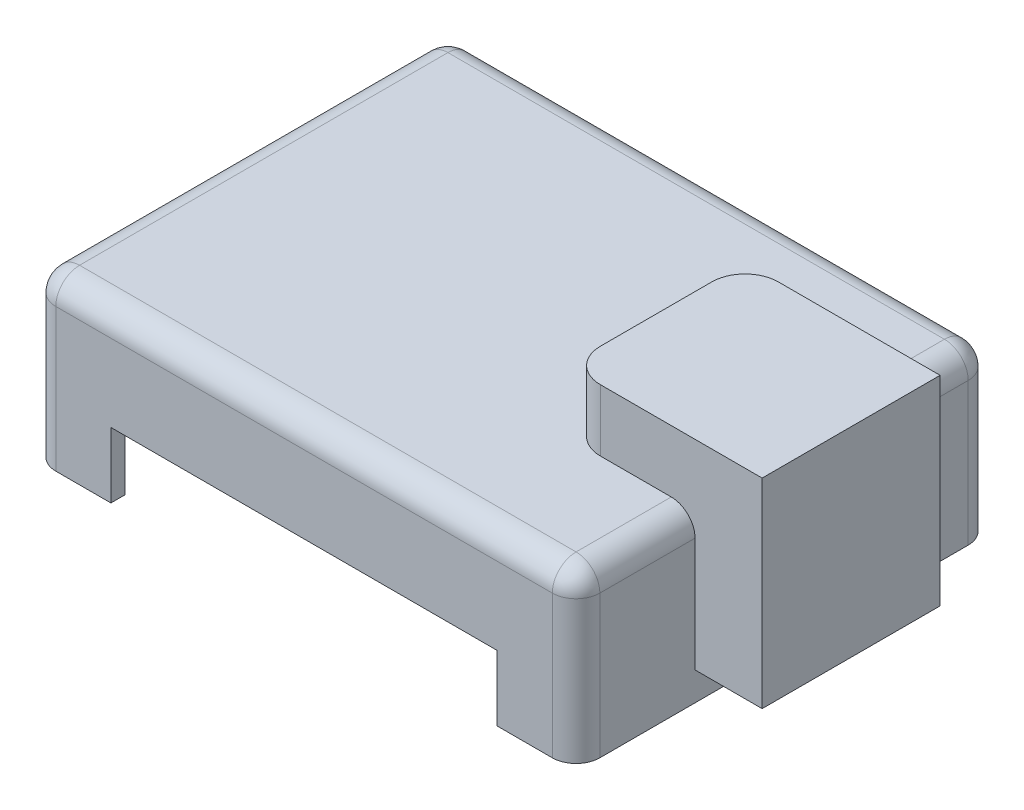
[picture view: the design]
ISO-10303-21;
HEADER;
FILE_DESCRIPTION(('STEP AP214'),'2;1');
FILE_NAME('part.step','',(''),(''),'','','');
FILE_SCHEMA(('AUTOMOTIVE_DESIGN { 1 0 10303 214 1 1 1 1 }'));
ENDSEC;
DATA;
#1=APPLICATION_CONTEXT('core data for automotive mechanical design processes');
#2=APPLICATION_PROTOCOL_DEFINITION('international standard','automotive_design',2000,#1);
#3=PRODUCT_CONTEXT('',#1,'mechanical');
#4=PRODUCT('Part','Part','',(#3));
#5=PRODUCT_RELATED_PRODUCT_CATEGORY('part','',(#4));
#6=PRODUCT_DEFINITION_FORMATION('','',#4);
#7=PRODUCT_DEFINITION_CONTEXT('part definition',#1,'design');
#8=PRODUCT_DEFINITION('design','',#6,#7);
#9=PRODUCT_DEFINITION_SHAPE('','',#8);
#10=(LENGTH_UNIT() NAMED_UNIT(*) SI_UNIT(.MILLI.,.METRE.));
#11=(NAMED_UNIT(*) PLANE_ANGLE_UNIT() SI_UNIT($,.RADIAN.));
#12=(NAMED_UNIT(*) SI_UNIT($,.STERADIAN.) SOLID_ANGLE_UNIT());
#13=UNCERTAINTY_MEASURE_WITH_UNIT(LENGTH_MEASURE(1.E-05),#10,'distance_accuracy_value','');
#14=(GEOMETRIC_REPRESENTATION_CONTEXT(3) GLOBAL_UNCERTAINTY_ASSIGNED_CONTEXT((#13)) GLOBAL_UNIT_ASSIGNED_CONTEXT((#10,
#11,#12)) REPRESENTATION_CONTEXT('',''));
#15=CARTESIAN_POINT('',(0.,0.,0.));
#16=DIRECTION('',(0.,0.,1.));
#17=DIRECTION('',(1.,0.,0.));
#18=AXIS2_PLACEMENT_3D('',#15,#16,#17);
#19=CARTESIAN_POINT('',(71.3184047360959,48.,-18.7130463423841));
#20=DIRECTION('',(-1.,0.,0.));
#21=DIRECTION('',(0.,0.,1.));
#22=AXIS2_PLACEMENT_3D('',#19,#20,#21);
#23=PLANE('',#22);
#24=DIRECTION('',(0.,-1.,0.));
#25=VECTOR('',#24,1.);
#26=CARTESIAN_POINT('',(71.3184047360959,48.,18.7130463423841));
#27=LINE('',#26,#25);
#28=CARTESIAN_POINT('',(71.3184047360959,48.,18.7130463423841));
#29=VERTEX_POINT('',#28);
#30=CARTESIAN_POINT('',(71.3184047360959,6.00000000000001,18.7130463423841));
#31=VERTEX_POINT('',#30);
#32=EDGE_CURVE('E114',#29,#31,#27,.T.);
#33=ORIENTED_EDGE('',*,*,#32,.T.);
#34=DIRECTION('',(0.,0.,-1.));
#35=VECTOR('',#34,1.);
#36=CARTESIAN_POINT('',(71.3184047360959,6.00000000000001,-18.7130463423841));
#37=LINE('',#36,#35);
#38=CARTESIAN_POINT('',(71.3184047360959,6.00000000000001,-18.7130463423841));
#39=VERTEX_POINT('',#38);
#40=EDGE_CURVE('E108',#31,#39,#37,.T.);
#41=ORIENTED_EDGE('',*,*,#40,.T.);
#42=DIRECTION('',(0.,-1.,0.));
#43=VECTOR('',#42,1.);
#44=CARTESIAN_POINT('',(71.3184047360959,48.,-18.7130463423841));
#45=LINE('',#44,#43);
#46=CARTESIAN_POINT('',(71.3184047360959,48.,-18.7130463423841));
#47=VERTEX_POINT('',#46);
#48=EDGE_CURVE('E12',#47,#39,#45,.T.);
#49=ORIENTED_EDGE('',*,*,#48,.F.);
#50=DIRECTION('',(0.,0.,-1.));
#51=VECTOR('',#50,1.);
#52=CARTESIAN_POINT('',(71.3184047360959,48.,-18.7130463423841));
#53=LINE('',#52,#51);
#54=EDGE_CURVE('E126',#29,#47,#53,.T.);
#55=ORIENTED_EDGE('',*,*,#54,.F.);
#56=EDGE_LOOP('',(#33,#41,#49,#55));
#57=FACE_BOUND('',#56,.T.);
#58=ADVANCED_FACE('F44',(#57),#23,.F.);
#59=CARTESIAN_POINT('',(37.3006394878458,48.,-18.7130463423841));
#60=DIRECTION('',(0.,0.,1.));
#61=DIRECTION('',(1.,0.,0.));
#62=AXIS2_PLACEMENT_3D('',#59,#60,#61);
#63=PLANE('',#62);
#64=ORIENTED_EDGE('',*,*,#48,.T.);
#65=DIRECTION('',(-1.,0.,0.));
#66=VECTOR('',#65,1.);
#67=CARTESIAN_POINT('',(37.3006394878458,6.00000000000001,-18.7130463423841));
#68=LINE('',#67,#66);
#69=CARTESIAN_POINT('',(37.3006394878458,6.00000000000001,-18.7130463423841));
#70=VERTEX_POINT('',#69);
#71=EDGE_CURVE('E98',#39,#70,#68,.T.);
#72=ORIENTED_EDGE('',*,*,#71,.T.);
#73=DIRECTION('',(0.,-1.,0.));
#74=VECTOR('',#73,1.);
#75=CARTESIAN_POINT('',(37.3006394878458,48.,-18.7130463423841));
#76=LINE('',#75,#74);
#77=CARTESIAN_POINT('',(37.3006394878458,48.,-18.7130463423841));
#78=VERTEX_POINT('',#77);
#79=EDGE_CURVE('E51',#78,#70,#76,.T.);
#80=ORIENTED_EDGE('',*,*,#79,.F.);
#81=DIRECTION('',(-1.,0.,0.));
#82=VECTOR('',#81,1.);
#83=CARTESIAN_POINT('',(37.3006394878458,48.,-18.7130463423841));
#84=LINE('',#83,#82);
#85=EDGE_CURVE('E99',#47,#78,#84,.T.);
#86=ORIENTED_EDGE('',*,*,#85,.F.);
#87=EDGE_LOOP('',(#64,#72,#80,#86));
#88=FACE_BOUND('',#87,.T.);
#89=ADVANCED_FACE('F96',(#88),#63,.F.);
#90=CARTESIAN_POINT('',(37.3006394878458,48.,-11.7130463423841));
#91=DIRECTION('',(0.,-1.,0.));
#92=DIRECTION('',(0.,0.,-1.));
#93=AXIS2_PLACEMENT_3D('',#90,#91,#92);
#94=CYLINDRICAL_SURFACE('',#93,7.);
#95=ORIENTED_EDGE('',*,*,#79,.T.);
#96=CARTESIAN_POINT('',(37.3006394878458,6.00000000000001,-11.7130463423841));
#97=DIRECTION('',(0.,1.,0.));
#98=DIRECTION('',(0.,0.,1.));
#99=AXIS2_PLACEMENT_3D('',#96,#97,#98);
#100=CIRCLE('',#99,7.);
#101=CARTESIAN_POINT('',(30.3006394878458,6.00000000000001,-11.7130463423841));
#102=VERTEX_POINT('',#101);
#103=EDGE_CURVE('E112',#70,#102,#100,.T.);
#104=ORIENTED_EDGE('',*,*,#103,.T.);
#105=DIRECTION('',(0.,-1.,0.));
#106=VECTOR('',#105,1.);
#107=CARTESIAN_POINT('',(30.3006394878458,48.,-11.7130463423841));
#108=LINE('',#107,#106);
#109=CARTESIAN_POINT('',(30.3006394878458,48.,-11.7130463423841));
#110=VERTEX_POINT('',#109);
#111=EDGE_CURVE('E140',#110,#102,#108,.T.);
#112=ORIENTED_EDGE('',*,*,#111,.F.);
#113=CARTESIAN_POINT('',(37.3006394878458,48.,-11.7130463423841));
#114=DIRECTION('',(0.,1.,0.));
#115=DIRECTION('',(0.,0.,1.));
#116=AXIS2_PLACEMENT_3D('',#113,#114,#115);
#117=CIRCLE('',#116,7.);
#118=EDGE_CURVE('E129',#78,#110,#117,.T.);
#119=ORIENTED_EDGE('',*,*,#118,.F.);
#120=EDGE_LOOP('',(#95,#104,#112,#119));
#121=FACE_BOUND('',#120,.T.);
#122=ADVANCED_FACE('F143',(#121),#94,.T.);
#123=CARTESIAN_POINT('',(30.3006394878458,48.,-11.7130463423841));
#124=DIRECTION('',(1.,0.,0.));
#125=DIRECTION('',(0.,0.,-1.));
#126=AXIS2_PLACEMENT_3D('',#123,#124,#125);
#127=PLANE('',#126);
#128=ORIENTED_EDGE('',*,*,#111,.T.);
#129=DIRECTION('',(0.,0.,1.));
#130=VECTOR('',#129,1.);
#131=CARTESIAN_POINT('',(30.3006394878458,6.00000000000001,-11.7130463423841));
#132=LINE('',#131,#130);
#133=CARTESIAN_POINT('',(30.3006394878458,6.00000000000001,11.7130463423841));
#134=VERTEX_POINT('',#133);
#135=EDGE_CURVE('E118',#102,#134,#132,.T.);
#136=ORIENTED_EDGE('',*,*,#135,.T.);
#137=DIRECTION('',(0.,-1.,0.));
#138=VECTOR('',#137,1.);
#139=CARTESIAN_POINT('',(30.3006394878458,48.,11.7130463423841));
#140=LINE('',#139,#138);
#141=CARTESIAN_POINT('',(30.3006394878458,48.,11.7130463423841));
#142=VERTEX_POINT('',#141);
#143=EDGE_CURVE('E138',#142,#134,#140,.T.);
#144=ORIENTED_EDGE('',*,*,#143,.F.);
#145=DIRECTION('',(0.,0.,1.));
#146=VECTOR('',#145,1.);
#147=CARTESIAN_POINT('',(30.3006394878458,48.,-11.7130463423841));
#148=LINE('',#147,#146);
#149=EDGE_CURVE('E131',#110,#142,#148,.T.);
#150=ORIENTED_EDGE('',*,*,#149,.F.);
#151=EDGE_LOOP('',(#128,#136,#144,#150));
#152=FACE_BOUND('',#151,.T.);
#153=ADVANCED_FACE('F149',(#152),#127,.F.);
#154=CARTESIAN_POINT('',(37.3006394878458,48.,11.7130463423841));
#155=DIRECTION('',(0.,-1.,0.));
#156=DIRECTION('',(0.,0.,-1.));
#157=AXIS2_PLACEMENT_3D('',#154,#155,#156);
#158=CYLINDRICAL_SURFACE('',#157,7.);
#159=ORIENTED_EDGE('',*,*,#143,.T.);
#160=CARTESIAN_POINT('',(37.3006394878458,6.00000000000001,11.7130463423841));
#161=DIRECTION('',(0.,1.,0.));
#162=DIRECTION('',(0.,0.,1.));
#163=AXIS2_PLACEMENT_3D('',#160,#161,#162);
#164=CIRCLE('',#163,7.);
#165=CARTESIAN_POINT('',(37.3006394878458,6.00000000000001,18.7130463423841));
#166=VERTEX_POINT('',#165);
#167=EDGE_CURVE('E121',#134,#166,#164,.T.);
#168=ORIENTED_EDGE('',*,*,#167,.T.);
#169=DIRECTION('',(0.,-1.,0.));
#170=VECTOR('',#169,1.);
#171=CARTESIAN_POINT('',(37.3006394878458,48.,18.7130463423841));
#172=LINE('',#171,#170);
#173=CARTESIAN_POINT('',(37.3006394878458,48.,18.7130463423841));
#174=VERTEX_POINT('',#173);
#175=EDGE_CURVE('E136',#174,#166,#172,.T.);
#176=ORIENTED_EDGE('',*,*,#175,.F.);
#177=CARTESIAN_POINT('',(37.3006394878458,48.,11.7130463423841));
#178=DIRECTION('',(0.,1.,0.));
#179=DIRECTION('',(0.,0.,1.));
#180=AXIS2_PLACEMENT_3D('',#177,#178,#179);
#181=CIRCLE('',#180,7.);
#182=EDGE_CURVE('E63',#142,#174,#181,.T.);
#183=ORIENTED_EDGE('',*,*,#182,.F.);
#184=EDGE_LOOP('',(#159,#168,#176,#183));
#185=FACE_BOUND('',#184,.T.);
#186=ADVANCED_FACE('F152',(#185),#158,.T.);
#187=CARTESIAN_POINT('',(37.3006394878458,48.,18.7130463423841));
#188=DIRECTION('',(0.,0.,-1.));
#189=DIRECTION('',(-1.,0.,0.));
#190=AXIS2_PLACEMENT_3D('',#187,#188,#189);
#191=PLANE('',#190);
#192=ORIENTED_EDGE('',*,*,#175,.T.);
#193=DIRECTION('',(1.,0.,0.));
#194=VECTOR('',#193,1.);
#195=CARTESIAN_POINT('',(37.3006394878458,6.00000000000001,18.7130463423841));
#196=LINE('',#195,#194);
#197=EDGE_CURVE('E124',#166,#31,#196,.T.);
#198=ORIENTED_EDGE('',*,*,#197,.T.);
#199=ORIENTED_EDGE('',*,*,#32,.F.);
#200=DIRECTION('',(1.,0.,0.));
#201=VECTOR('',#200,1.);
#202=CARTESIAN_POINT('',(37.3006394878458,48.,18.7130463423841));
#203=LINE('',#202,#201);
#204=EDGE_CURVE('E58',#174,#29,#203,.T.);
#205=ORIENTED_EDGE('',*,*,#204,.F.);
#206=EDGE_LOOP('',(#192,#198,#199,#205));
#207=FACE_BOUND('',#206,.T.);
#208=ADVANCED_FACE('F154',(#207),#191,.F.);
#209=CARTESIAN_POINT('',(37.3006394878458,48.,11.7130463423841));
#210=DIRECTION('',(0.,1.,0.));
#211=DIRECTION('',(0.,0.,1.));
#212=AXIS2_PLACEMENT_3D('',#209,#210,#211);
#213=PLANE('',#212);
#214=ORIENTED_EDGE('',*,*,#54,.T.);
#215=ORIENTED_EDGE('',*,*,#85,.T.);
#216=ORIENTED_EDGE('',*,*,#118,.T.);
#217=ORIENTED_EDGE('',*,*,#149,.T.);
#218=ORIENTED_EDGE('',*,*,#182,.T.);
#219=ORIENTED_EDGE('',*,*,#204,.T.);
#220=EDGE_LOOP('',(#214,#215,#216,#217,#218,#219));
#221=FACE_BOUND('',#220,.T.);
#222=ADVANCED_FACE('F146',(#221),#213,.T.);
#223=CARTESIAN_POINT('',(37.3006394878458,6.00000000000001,11.7130463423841));
#224=DIRECTION('',(0.,1.,0.));
#225=DIRECTION('',(0.,0.,1.));
#226=AXIS2_PLACEMENT_3D('',#223,#224,#225);
#227=PLANE('',#226);
#228=ORIENTED_EDGE('',*,*,#40,.F.);
#229=ORIENTED_EDGE('',*,*,#197,.F.);
#230=ORIENTED_EDGE('',*,*,#167,.F.);
#231=ORIENTED_EDGE('',*,*,#135,.F.);
#232=ORIENTED_EDGE('',*,*,#103,.F.);
#233=ORIENTED_EDGE('',*,*,#71,.F.);
#234=EDGE_LOOP('',(#228,#229,#230,#231,#232,#233));
#235=FACE_BOUND('',#234,.T.);
#236=ADVANCED_FACE('F106',(#235),#227,.F.);
#237=CLOSED_SHELL('',(#58,#89,#122,#153,#186,#208,#222,#236));
#238=MANIFOLD_SOLID_BREP('B2_NOT_SHOWN',#237);
#239=CARTESIAN_POINT('',(57.2074120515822,35.,-43.7327831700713));
#240=DIRECTION('',(-1.,0.,0.));
#241=DIRECTION('',(0.,0.,1.));
#242=AXIS2_PLACEMENT_3D('',#239,#240,#241);
#243=PLANE('',#242);
#244=DIRECTION('',(0.,1.,0.));
#245=VECTOR('',#244,1.);
#246=CARTESIAN_POINT('',(57.2074120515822,35.,-18.7130463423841));
#247=LINE('',#246,#245);
#248=CARTESIAN_POINT('',(57.2074120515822,6.00000000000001,-18.7130463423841));
#249=VERTEX_POINT('',#248);
#250=CARTESIAN_POINT('',(57.2074120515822,30.,-18.7130463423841));
#251=VERTEX_POINT('',#250);
#252=EDGE_CURVE('E451',#249,#251,#247,.T.);
#253=ORIENTED_EDGE('',*,*,#252,.F.);
#254=DIRECTION('',(0.,0.,-1.));
#255=VECTOR('',#254,1.);
#256=CARTESIAN_POINT('',(57.2074120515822,6.00000000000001,-43.7327831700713));
#257=LINE('',#256,#255);
#258=CARTESIAN_POINT('',(57.2074120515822,6.00000000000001,18.7130463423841));
#259=VERTEX_POINT('',#258);
#260=EDGE_CURVE('E485',#259,#249,#257,.T.);
#261=ORIENTED_EDGE('',*,*,#260,.F.);
#262=DIRECTION('',(0.,-1.,0.));
#263=VECTOR('',#262,1.);
#264=CARTESIAN_POINT('',(57.2074120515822,35.,18.7130463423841));
#265=LINE('',#264,#263);
#266=CARTESIAN_POINT('',(57.2074120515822,30.,18.7130463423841));
#267=VERTEX_POINT('',#266);
#268=EDGE_CURVE('E463',#267,#259,#265,.T.);
#269=ORIENTED_EDGE('',*,*,#268,.F.);
#270=DIRECTION('',(0.,0.,-1.));
#271=VECTOR('',#270,1.);
#272=CARTESIAN_POINT('',(57.2074120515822,30.,43.7327831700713));
#273=LINE('',#272,#271);
#274=CARTESIAN_POINT('',(57.2074120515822,30.,38.7327831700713));
#275=VERTEX_POINT('',#274);
#276=EDGE_CURVE('E673',#267,#275,#273,.F.);
#277=ORIENTED_EDGE('',*,*,#276,.T.);
#278=DIRECTION('',(0.,-1.,0.));
#279=VECTOR('',#278,1.);
#280=CARTESIAN_POINT('',(57.2074120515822,35.,38.7327831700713));
#281=LINE('',#280,#279);
#282=CARTESIAN_POINT('',(57.2074120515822,0.,38.7327831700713));
#283=VERTEX_POINT('',#282);
#284=EDGE_CURVE('E671',#275,#283,#281,.T.);
#285=ORIENTED_EDGE('',*,*,#284,.T.);
#286=DIRECTION('',(0.,0.,-1.));
#287=VECTOR('',#286,1.);
#288=CARTESIAN_POINT('',(57.2074120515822,0.,-43.7327831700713));
#289=LINE('',#288,#287);
#290=CARTESIAN_POINT('',(57.2074120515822,0.,-38.7327831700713));
#291=VERTEX_POINT('',#290);
#292=EDGE_CURVE('E649',#283,#291,#289,.T.);
#293=ORIENTED_EDGE('',*,*,#292,.T.);
#294=DIRECTION('',(0.,-1.,0.));
#295=VECTOR('',#294,1.);
#296=CARTESIAN_POINT('',(57.2074120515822,35.,-38.7327831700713));
#297=LINE('',#296,#295);
#298=CARTESIAN_POINT('',(57.2074120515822,30.,-38.7327831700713));
#299=VERTEX_POINT('',#298);
#300=EDGE_CURVE('E677',#291,#299,#297,.F.);
#301=ORIENTED_EDGE('',*,*,#300,.T.);
#302=EDGE_CURVE('E674',#299,#251,#273,.F.);
#303=ORIENTED_EDGE('',*,*,#302,.T.);
#304=EDGE_LOOP('',(#253,#261,#269,#277,#285,#293,#301,#303));
#305=FACE_BOUND('',#304,.T.);
#306=ADVANCED_FACE('F219',(#305),#243,.F.);
#307=CARTESIAN_POINT('',(-57.2074120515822,35.,43.7327831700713));
#308=DIRECTION('',(0.,1.,0.));
#309=DIRECTION('',(0.,0.,1.));
#310=AXIS2_PLACEMENT_3D('',#307,#308,#309);
#311=PLANE('',#310);
#312=CARTESIAN_POINT('',(37.3006394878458,35.,-11.7130463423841));
#313=DIRECTION('',(0.,1.,0.));
#314=DIRECTION('',(0.,0.,1.));
#315=AXIS2_PLACEMENT_3D('',#312,#313,#314);
#316=CIRCLE('',#315,7.);
#317=CARTESIAN_POINT('',(30.3006394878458,35.,-11.7130463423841));
#318=VERTEX_POINT('',#317);
#319=CARTESIAN_POINT('',(37.3006394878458,35.,-18.7130463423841));
#320=VERTEX_POINT('',#319);
#321=EDGE_CURVE('E483',#318,#320,#316,.F.);
#322=ORIENTED_EDGE('',*,*,#321,.T.);
#323=DIRECTION('',(1.,0.,0.));
#324=VECTOR('',#323,1.);
#325=CARTESIAN_POINT('',(-57.2074120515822,35.,-18.7130463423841));
#326=LINE('',#325,#324);
#327=CARTESIAN_POINT('',(52.2074120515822,35.,-18.7130463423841));
#328=VERTEX_POINT('',#327);
#329=EDGE_CURVE('E478',#320,#328,#326,.T.);
#330=ORIENTED_EDGE('',*,*,#329,.T.);
#331=DIRECTION('',(0.,0.,-1.));
#332=VECTOR('',#331,1.);
#333=CARTESIAN_POINT('',(52.2074120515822,35.,-43.7327831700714));
#334=LINE('',#333,#332);
#335=CARTESIAN_POINT('',(52.2074120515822,35.,-38.7327831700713));
#336=VERTEX_POINT('',#335);
#337=EDGE_CURVE('E659',#328,#336,#334,.T.);
#338=ORIENTED_EDGE('',*,*,#337,.T.);
#339=DIRECTION('',(-1.,0.,0.));
#340=VECTOR('',#339,1.);
#341=CARTESIAN_POINT('',(-57.2074120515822,35.,-38.7327831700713));
#342=LINE('',#341,#340);
#343=CARTESIAN_POINT('',(-52.2074120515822,35.,-38.7327831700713));
#344=VERTEX_POINT('',#343);
#345=EDGE_CURVE('E661',#336,#344,#342,.T.);
#346=ORIENTED_EDGE('',*,*,#345,.T.);
#347=DIRECTION('',(0.,0.,1.));
#348=VECTOR('',#347,1.);
#349=CARTESIAN_POINT('',(-52.2074120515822,35.,43.7327831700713));
#350=LINE('',#349,#348);
#351=CARTESIAN_POINT('',(-52.2074120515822,35.,38.7327831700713));
#352=VERTEX_POINT('',#351);
#353=EDGE_CURVE('E655',#344,#352,#350,.T.);
#354=ORIENTED_EDGE('',*,*,#353,.T.);
#355=DIRECTION('',(1.,0.,0.));
#356=VECTOR('',#355,1.);
#357=CARTESIAN_POINT('',(57.2074120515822,35.,38.7327831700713));
#358=LINE('',#357,#356);
#359=CARTESIAN_POINT('',(52.2074120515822,35.,38.7327831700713));
#360=VERTEX_POINT('',#359);
#361=EDGE_CURVE('E657',#352,#360,#358,.T.);
#362=ORIENTED_EDGE('',*,*,#361,.T.);
#363=CARTESIAN_POINT('',(52.2074120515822,35.,18.7130463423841));
#364=VERTEX_POINT('',#363);
#365=EDGE_CURVE('E462',#360,#364,#334,.T.);
#366=ORIENTED_EDGE('',*,*,#365,.T.);
#367=DIRECTION('',(-1.,0.,0.));
#368=VECTOR('',#367,1.);
#369=CARTESIAN_POINT('',(-57.2074120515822,35.,18.7130463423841));
#370=LINE('',#369,#368);
#371=CARTESIAN_POINT('',(37.3006394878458,35.,18.7130463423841));
#372=VERTEX_POINT('',#371);
#373=EDGE_CURVE('E234',#364,#372,#370,.T.);
#374=ORIENTED_EDGE('',*,*,#373,.T.);
#375=CARTESIAN_POINT('',(37.3006394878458,35.,11.7130463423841));
#376=DIRECTION('',(0.,1.,0.));
#377=DIRECTION('',(0.,0.,1.));
#378=AXIS2_PLACEMENT_3D('',#375,#376,#377);
#379=CIRCLE('',#378,7.);
#380=CARTESIAN_POINT('',(30.3006394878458,35.,11.7130463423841));
#381=VERTEX_POINT('',#380);
#382=EDGE_CURVE('E442',#372,#381,#379,.F.);
#383=ORIENTED_EDGE('',*,*,#382,.T.);
#384=DIRECTION('',(0.,0.,-1.));
#385=VECTOR('',#384,1.);
#386=CARTESIAN_POINT('',(30.3006394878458,35.,43.7327831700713));
#387=LINE('',#386,#385);
#388=EDGE_CURVE('E450',#381,#318,#387,.T.);
#389=ORIENTED_EDGE('',*,*,#388,.T.);
#390=EDGE_LOOP('',(#322,#330,#338,#346,#354,#362,#366,#374,#383,#389));
#391=FACE_BOUND('',#390,.T.);
#392=ADVANCED_FACE('F460',(#391),#311,.T.);
#393=CARTESIAN_POINT('',(52.2074120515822,30.,43.7327831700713));
#394=DIRECTION('',(0.,0.,1.));
#395=DIRECTION('',(1.,0.,0.));
#396=AXIS2_PLACEMENT_3D('',#393,#394,#395);
#397=CYLINDRICAL_SURFACE('',#396,5.);
#398=ORIENTED_EDGE('',*,*,#337,.F.);
#399=CARTESIAN_POINT('',(52.2074120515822,30.,-18.7130463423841));
#400=DIRECTION('',(0.,0.,1.));
#401=DIRECTION('',(1.,0.,0.));
#402=AXIS2_PLACEMENT_3D('',#399,#400,#401);
#403=CIRCLE('',#402,5.);
#404=EDGE_CURVE('E475',#328,#251,#403,.F.);
#405=ORIENTED_EDGE('',*,*,#404,.T.);
#406=ORIENTED_EDGE('',*,*,#302,.F.);
#407=CARTESIAN_POINT('',(52.2074120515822,30.,-38.7327831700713));
#408=DIRECTION('',(0.,0.,-1.));
#409=DIRECTION('',(-1.,0.,0.));
#410=AXIS2_PLACEMENT_3D('',#407,#408,#409);
#411=CIRCLE('',#410,5.);
#412=EDGE_CURVE('E618',#336,#299,#411,.T.);
#413=ORIENTED_EDGE('',*,*,#412,.F.);
#414=EDGE_LOOP('',(#398,#405,#406,#413));
#415=FACE_BOUND('',#414,.T.);
#416=ADVANCED_FACE('F776',(#415),#397,.T.);
#417=ORIENTED_EDGE('',*,*,#276,.F.);
#418=CARTESIAN_POINT('',(52.2074120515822,30.,18.7130463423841));
#419=DIRECTION('',(0.,0.,-1.));
#420=DIRECTION('',(-1.,0.,0.));
#421=AXIS2_PLACEMENT_3D('',#418,#419,#420);
#422=CIRCLE('',#421,5.);
#423=EDGE_CURVE('E464',#267,#364,#422,.F.);
#424=ORIENTED_EDGE('',*,*,#423,.T.);
#425=ORIENTED_EDGE('',*,*,#365,.F.);
#426=CARTESIAN_POINT('',(52.2074120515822,30.,38.7327831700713));
#427=DIRECTION('',(0.,0.,1.));
#428=DIRECTION('',(1.,0.,0.));
#429=AXIS2_PLACEMENT_3D('',#426,#427,#428);
#430=CIRCLE('',#429,5.);
#431=EDGE_CURVE('E627',#360,#275,#430,.F.);
#432=ORIENTED_EDGE('',*,*,#431,.T.);
#433=EDGE_LOOP('',(#417,#424,#425,#432));
#434=FACE_BOUND('',#433,.T.);
#435=ADVANCED_FACE('F835',(#434),#397,.T.);
#436=CARTESIAN_POINT('',(54.2074120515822,35.,-43.7327831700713));
#437=DIRECTION('',(-1.,0.,0.));
#438=DIRECTION('',(0.,0.,1.));
#439=AXIS2_PLACEMENT_3D('',#436,#437,#438);
#440=PLANE('',#439);
#441=DIRECTION('',(0.,0.,-1.));
#442=VECTOR('',#441,1.);
#443=CARTESIAN_POINT('',(54.2074120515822,6.00000000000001,-43.7327831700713));
#444=LINE('',#443,#442);
#445=CARTESIAN_POINT('',(54.2074120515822,6.00000000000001,18.7130463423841));
#446=VERTEX_POINT('',#445);
#447=CARTESIAN_POINT('',(54.2074120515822,6.00000000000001,-18.7130463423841));
#448=VERTEX_POINT('',#447);
#449=EDGE_CURVE('E42',#446,#448,#444,.T.);
#450=ORIENTED_EDGE('',*,*,#449,.T.);
#451=DIRECTION('',(0.,1.,0.));
#452=VECTOR('',#451,1.);
#453=CARTESIAN_POINT('',(54.2074120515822,35.,-18.7130463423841));
#454=LINE('',#453,#452);
#455=CARTESIAN_POINT('',(54.2074120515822,30.,-18.7130463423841));
#456=VERTEX_POINT('',#455);
#457=EDGE_CURVE('E472',#448,#456,#454,.T.);
#458=ORIENTED_EDGE('',*,*,#457,.T.);
#459=DIRECTION('',(0.,0.,1.));
#460=VECTOR('',#459,1.);
#461=CARTESIAN_POINT('',(54.2074120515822,30.,-43.7327831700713));
#462=LINE('',#461,#460);
#463=CARTESIAN_POINT('',(54.2074120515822,30.,-38.7327831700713));
#464=VERTEX_POINT('',#463);
#465=EDGE_CURVE('E544',#464,#456,#462,.T.);
#466=ORIENTED_EDGE('',*,*,#465,.F.);
#467=DIRECTION('',(0.,1.,0.));
#468=VECTOR('',#467,1.);
#469=CARTESIAN_POINT('',(54.2074120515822,35.,-38.7327831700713));
#470=LINE('',#469,#468);
#471=CARTESIAN_POINT('',(54.2074120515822,0.,-38.7327831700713));
#472=VERTEX_POINT('',#471);
#473=EDGE_CURVE('E526',#472,#464,#470,.T.);
#474=ORIENTED_EDGE('',*,*,#473,.F.);
#475=DIRECTION('',(0.,0.,-1.));
#476=VECTOR('',#475,1.);
#477=CARTESIAN_POINT('',(54.2074120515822,0.,-43.7327831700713));
#478=LINE('',#477,#476);
#479=CARTESIAN_POINT('',(54.2074120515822,0.,38.7327831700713));
#480=VERTEX_POINT('',#479);
#481=EDGE_CURVE('E598',#480,#472,#478,.T.);
#482=ORIENTED_EDGE('',*,*,#481,.F.);
#483=DIRECTION('',(0.,1.,0.));
#484=VECTOR('',#483,1.);
#485=CARTESIAN_POINT('',(54.2074120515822,35.,38.7327831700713));
#486=LINE('',#485,#484);
#487=CARTESIAN_POINT('',(54.2074120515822,30.,38.7327831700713));
#488=VERTEX_POINT('',#487);
#489=EDGE_CURVE('E534',#488,#480,#486,.F.);
#490=ORIENTED_EDGE('',*,*,#489,.F.);
#491=CARTESIAN_POINT('',(54.2074120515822,30.,18.7130463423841));
#492=VERTEX_POINT('',#491);
#493=EDGE_CURVE('E536',#492,#488,#462,.T.);
#494=ORIENTED_EDGE('',*,*,#493,.F.);
#495=DIRECTION('',(0.,-1.,0.));
#496=VECTOR('',#495,1.);
#497=CARTESIAN_POINT('',(54.2074120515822,35.,18.7130463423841));
#498=LINE('',#497,#496);
#499=EDGE_CURVE('E241',#492,#446,#498,.T.);
#500=ORIENTED_EDGE('',*,*,#499,.T.);
#501=EDGE_LOOP('',(#450,#458,#466,#474,#482,#490,#494,#500));
#502=FACE_BOUND('',#501,.T.);
#503=ADVANCED_FACE('F750',(#502),#440,.T.);
#504=CARTESIAN_POINT('',(-57.2074120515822,32.,43.7327831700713));
#505=DIRECTION('',(0.,1.,0.));
#506=DIRECTION('',(0.,0.,1.));
#507=AXIS2_PLACEMENT_3D('',#504,#505,#506);
#508=PLANE('',#507);
#509=DIRECTION('',(1.,0.,0.));
#510=VECTOR('',#509,1.);
#511=CARTESIAN_POINT('',(-57.2074120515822,32.,-18.7130463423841));
#512=LINE('',#511,#510);
#513=CARTESIAN_POINT('',(37.3006394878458,32.,-18.7130463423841));
#514=VERTEX_POINT('',#513);
#515=CARTESIAN_POINT('',(52.2074120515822,32.,-18.7130463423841));
#516=VERTEX_POINT('',#515);
#517=EDGE_CURVE('E466',#514,#516,#512,.T.);
#518=ORIENTED_EDGE('',*,*,#517,.F.);
#519=CARTESIAN_POINT('',(37.3006394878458,32.,-11.7130463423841));
#520=DIRECTION('',(0.,1.,0.));
#521=DIRECTION('',(0.,0.,1.));
#522=AXIS2_PLACEMENT_3D('',#519,#520,#521);
#523=CIRCLE('',#522,7.);
#524=CARTESIAN_POINT('',(30.3006394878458,32.,-11.7130463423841));
#525=VERTEX_POINT('',#524);
#526=EDGE_CURVE('E227',#525,#514,#523,.F.);
#527=ORIENTED_EDGE('',*,*,#526,.F.);
#528=DIRECTION('',(0.,0.,-1.));
#529=VECTOR('',#528,1.);
#530=CARTESIAN_POINT('',(30.3006394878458,32.,43.7327831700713));
#531=LINE('',#530,#529);
#532=CARTESIAN_POINT('',(30.3006394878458,32.,11.7130463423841));
#533=VERTEX_POINT('',#532);
#534=EDGE_CURVE('E706',#533,#525,#531,.T.);
#535=ORIENTED_EDGE('',*,*,#534,.F.);
#536=CARTESIAN_POINT('',(37.3006394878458,32.,11.7130463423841));
#537=DIRECTION('',(0.,1.,0.));
#538=DIRECTION('',(0.,0.,1.));
#539=AXIS2_PLACEMENT_3D('',#536,#537,#538);
#540=CIRCLE('',#539,7.);
#541=CARTESIAN_POINT('',(37.3006394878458,32.,18.7130463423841));
#542=VERTEX_POINT('',#541);
#543=EDGE_CURVE('E704',#542,#533,#540,.F.);
#544=ORIENTED_EDGE('',*,*,#543,.F.);
#545=DIRECTION('',(-1.,0.,0.));
#546=VECTOR('',#545,1.);
#547=CARTESIAN_POINT('',(-57.2074120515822,32.,18.7130463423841));
#548=LINE('',#547,#546);
#549=CARTESIAN_POINT('',(52.2074120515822,32.,18.7130463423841));
#550=VERTEX_POINT('',#549);
#551=EDGE_CURVE('E455',#550,#542,#548,.T.);
#552=ORIENTED_EDGE('',*,*,#551,.F.);
#553=DIRECTION('',(0.,0.,1.));
#554=VECTOR('',#553,1.);
#555=CARTESIAN_POINT('',(52.2074120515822,32.,43.7327831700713));
#556=LINE('',#555,#554);
#557=CARTESIAN_POINT('',(52.2074120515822,32.,38.7327831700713));
#558=VERTEX_POINT('',#557);
#559=EDGE_CURVE('E552',#558,#550,#556,.F.);
#560=ORIENTED_EDGE('',*,*,#559,.F.);
#561=DIRECTION('',(1.,0.,0.));
#562=VECTOR('',#561,1.);
#563=CARTESIAN_POINT('',(-57.2074120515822,32.,38.7327831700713));
#564=LINE('',#563,#562);
#565=CARTESIAN_POINT('',(-52.2074120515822,32.,38.7327831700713));
#566=VERTEX_POINT('',#565);
#567=EDGE_CURVE('E562',#566,#558,#564,.T.);
#568=ORIENTED_EDGE('',*,*,#567,.F.);
#569=DIRECTION('',(0.,0.,1.));
#570=VECTOR('',#569,1.);
#571=CARTESIAN_POINT('',(-52.2074120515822,32.,43.7327831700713));
#572=LINE('',#571,#570);
#573=CARTESIAN_POINT('',(-52.2074120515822,32.,-38.7327831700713));
#574=VERTEX_POINT('',#573);
#575=EDGE_CURVE('E560',#574,#566,#572,.T.);
#576=ORIENTED_EDGE('',*,*,#575,.F.);
#577=DIRECTION('',(1.,0.,0.));
#578=VECTOR('',#577,1.);
#579=CARTESIAN_POINT('',(-57.2074120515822,32.,-38.7327831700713));
#580=LINE('',#579,#578);
#581=CARTESIAN_POINT('',(52.2074120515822,32.,-38.7327831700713));
#582=VERTEX_POINT('',#581);
#583=EDGE_CURVE('E555',#582,#574,#580,.F.);
#584=ORIENTED_EDGE('',*,*,#583,.F.);
#585=EDGE_CURVE('E556',#516,#582,#556,.F.);
#586=ORIENTED_EDGE('',*,*,#585,.F.);
#587=EDGE_LOOP('',(#518,#527,#535,#544,#552,#560,#568,#576,#584,#586));
#588=FACE_BOUND('',#587,.T.);
#589=ADVANCED_FACE('F724',(#588),#508,.F.);
#590=CARTESIAN_POINT('',(52.2074120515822,30.,43.7327831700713));
#591=DIRECTION('',(0.,0.,1.));
#592=DIRECTION('',(1.,0.,0.));
#593=AXIS2_PLACEMENT_3D('',#590,#591,#592);
#594=CYLINDRICAL_SURFACE('',#593,2.);
#595=CARTESIAN_POINT('',(52.2074120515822,30.,-18.7130463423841));
#596=DIRECTION('',(0.,0.,1.));
#597=DIRECTION('',(1.,0.,0.));
#598=AXIS2_PLACEMENT_3D('',#595,#596,#597);
#599=CIRCLE('',#598,2.);
#600=EDGE_CURVE('E702',#516,#456,#599,.F.);
#601=ORIENTED_EDGE('',*,*,#600,.F.);
#602=ORIENTED_EDGE('',*,*,#585,.T.);
#603=CARTESIAN_POINT('',(52.2074120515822,30.,-38.7327831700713));
#604=DIRECTION('',(0.,0.,1.));
#605=DIRECTION('',(1.,0.,0.));
#606=AXIS2_PLACEMENT_3D('',#603,#604,#605);
#607=CIRCLE('',#606,2.);
#608=EDGE_CURVE('E573',#582,#464,#607,.F.);
#609=ORIENTED_EDGE('',*,*,#608,.T.);
#610=ORIENTED_EDGE('',*,*,#465,.T.);
#611=EDGE_LOOP('',(#601,#602,#609,#610));
#612=FACE_BOUND('',#611,.T.);
#613=ADVANCED_FACE('F729',(#612),#594,.F.);
#614=CARTESIAN_POINT('',(52.2074120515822,30.,18.7130463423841));
#615=DIRECTION('',(0.,0.,-1.));
#616=DIRECTION('',(-1.,0.,0.));
#617=AXIS2_PLACEMENT_3D('',#614,#615,#616);
#618=CIRCLE('',#617,2.);
#619=EDGE_CURVE('E700',#492,#550,#618,.F.);
#620=ORIENTED_EDGE('',*,*,#619,.F.);
#621=ORIENTED_EDGE('',*,*,#493,.T.);
#622=CARTESIAN_POINT('',(52.2074120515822,30.,38.7327831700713));
#623=DIRECTION('',(0.,0.,1.));
#624=DIRECTION('',(1.,0.,0.));
#625=AXIS2_PLACEMENT_3D('',#622,#623,#624);
#626=CIRCLE('',#625,2.);
#627=EDGE_CURVE('E531',#558,#488,#626,.F.);
#628=ORIENTED_EDGE('',*,*,#627,.F.);
#629=ORIENTED_EDGE('',*,*,#559,.T.);
#630=EDGE_LOOP('',(#620,#621,#628,#629));
#631=FACE_BOUND('',#630,.T.);
#632=ADVANCED_FACE('F768',(#631),#594,.F.);
#633=CARTESIAN_POINT('',(-57.2074120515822,35.,-43.7327831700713));
#634=DIRECTION('',(1.,0.,0.));
#635=DIRECTION('',(0.,0.,-1.));
#636=AXIS2_PLACEMENT_3D('',#633,#634,#635);
#637=PLANE('',#636);
#638=DIRECTION('',(0.,0.,1.));
#639=VECTOR('',#638,1.);
#640=CARTESIAN_POINT('',(-57.2074120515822,30.,-43.7327831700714));
#641=LINE('',#640,#639);
#642=CARTESIAN_POINT('',(-57.2074120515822,30.,38.7327831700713));
#643=VERTEX_POINT('',#642);
#644=CARTESIAN_POINT('',(-57.2074120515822,30.,-38.7327831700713));
#645=VERTEX_POINT('',#644);
#646=EDGE_CURVE('E687',#643,#645,#641,.F.);
#647=ORIENTED_EDGE('',*,*,#646,.T.);
#648=DIRECTION('',(0.,-1.,0.));
#649=VECTOR('',#648,1.);
#650=CARTESIAN_POINT('',(-57.2074120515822,35.,-38.7327831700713));
#651=LINE('',#650,#649);
#652=CARTESIAN_POINT('',(-57.2074120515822,0.,-38.7327831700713));
#653=VERTEX_POINT('',#652);
#654=EDGE_CURVE('E689',#645,#653,#651,.T.);
#655=ORIENTED_EDGE('',*,*,#654,.T.);
#656=DIRECTION('',(0.,0.,1.));
#657=VECTOR('',#656,1.);
#658=CARTESIAN_POINT('',(-57.2074120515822,0.,-43.7327831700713));
#659=LINE('',#658,#657);
#660=CARTESIAN_POINT('',(-57.2074120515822,0.,38.7327831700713));
#661=VERTEX_POINT('',#660);
#662=EDGE_CURVE('E642',#653,#661,#659,.T.);
#663=ORIENTED_EDGE('',*,*,#662,.T.);
#664=DIRECTION('',(0.,-1.,0.));
#665=VECTOR('',#664,1.);
#666=CARTESIAN_POINT('',(-57.2074120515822,35.,38.7327831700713));
#667=LINE('',#666,#665);
#668=EDGE_CURVE('E685',#661,#643,#667,.F.);
#669=ORIENTED_EDGE('',*,*,#668,.T.);
#670=EDGE_LOOP('',(#647,#655,#663,#669));
#671=FACE_BOUND('',#670,.T.);
#672=ADVANCED_FACE('F221',(#671),#637,.F.);
#673=CARTESIAN_POINT('',(-57.2074120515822,35.,43.7327831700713));
#674=DIRECTION('',(0.,0.,-1.));
#675=DIRECTION('',(-1.,0.,0.));
#676=AXIS2_PLACEMENT_3D('',#673,#674,#675);
#677=PLANE('',#676);
#678=DIRECTION('',(1.,0.,0.));
#679=VECTOR('',#678,1.);
#680=CARTESIAN_POINT('',(-57.2074120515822,0.,43.7327831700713));
#681=LINE('',#680,#679);
#682=CARTESIAN_POINT('',(-52.2074120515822,0.,43.7327831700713));
#683=VERTEX_POINT('',#682);
#684=CARTESIAN_POINT('',(-40.6196419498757,0.,43.7327831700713));
#685=VERTEX_POINT('',#684);
#686=EDGE_CURVE('E646',#683,#685,#681,.T.);
#687=ORIENTED_EDGE('',*,*,#686,.T.);
#688=DIRECTION('',(0.,-1.,0.));
#689=VECTOR('',#688,1.);
#690=CARTESIAN_POINT('',(-40.6196419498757,0.,43.7327831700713));
#691=LINE('',#690,#689);
#692=CARTESIAN_POINT('',(-40.6196419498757,13.7609534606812,43.7327831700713));
#693=VERTEX_POINT('',#692);
#694=EDGE_CURVE('E495',#693,#685,#691,.T.);
#695=ORIENTED_EDGE('',*,*,#694,.F.);
#696=DIRECTION('',(-1.,0.,0.));
#697=VECTOR('',#696,1.);
#698=CARTESIAN_POINT('',(-40.6196419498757,13.7609534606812,43.7327831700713));
#699=LINE('',#698,#697);
#700=CARTESIAN_POINT('',(40.6196419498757,13.7609534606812,43.7327831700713));
#701=VERTEX_POINT('',#700);
#702=EDGE_CURVE('E488',#701,#693,#699,.T.);
#703=ORIENTED_EDGE('',*,*,#702,.F.);
#704=DIRECTION('',(0.,1.,0.));
#705=VECTOR('',#704,1.);
#706=CARTESIAN_POINT('',(40.6196419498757,0.,43.7327831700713));
#707=LINE('',#706,#705);
#708=CARTESIAN_POINT('',(40.6196419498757,0.,43.7327831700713));
#709=VERTEX_POINT('',#708);
#710=EDGE_CURVE('E492',#709,#701,#707,.T.);
#711=ORIENTED_EDGE('',*,*,#710,.F.);
#712=CARTESIAN_POINT('',(52.2074120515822,0.,43.7327831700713));
#713=VERTEX_POINT('',#712);
#714=EDGE_CURVE('E645',#709,#713,#681,.T.);
#715=ORIENTED_EDGE('',*,*,#714,.T.);
#716=DIRECTION('',(0.,-1.,0.));
#717=VECTOR('',#716,1.);
#718=CARTESIAN_POINT('',(52.2074120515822,35.,43.7327831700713));
#719=LINE('',#718,#717);
#720=CARTESIAN_POINT('',(52.2074120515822,30.,43.7327831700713));
#721=VERTEX_POINT('',#720);
#722=EDGE_CURVE('E683',#713,#721,#719,.F.);
#723=ORIENTED_EDGE('',*,*,#722,.T.);
#724=DIRECTION('',(1.,0.,0.));
#725=VECTOR('',#724,1.);
#726=CARTESIAN_POINT('',(-57.2074120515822,30.,43.7327831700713));
#727=LINE('',#726,#725);
#728=CARTESIAN_POINT('',(-52.2074120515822,30.,43.7327831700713));
#729=VERTEX_POINT('',#728);
#730=EDGE_CURVE('E681',#721,#729,#727,.F.);
#731=ORIENTED_EDGE('',*,*,#730,.T.);
#732=DIRECTION('',(0.,-1.,0.));
#733=VECTOR('',#732,1.);
#734=CARTESIAN_POINT('',(-52.2074120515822,35.,43.7327831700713));
#735=LINE('',#734,#733);
#736=EDGE_CURVE('E679',#729,#683,#735,.T.);
#737=ORIENTED_EDGE('',*,*,#736,.T.);
#738=EDGE_LOOP('',(#687,#695,#703,#711,#715,#723,#731,#737));
#739=FACE_BOUND('',#738,.T.);
#740=ADVANCED_FACE('F852',(#739),#677,.F.);
#741=CARTESIAN_POINT('',(-57.2074120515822,35.,-43.7327831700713));
#742=DIRECTION('',(0.,0.,1.));
#743=DIRECTION('',(1.,0.,0.));
#744=AXIS2_PLACEMENT_3D('',#741,#742,#743);
#745=PLANE('',#744);
#746=DIRECTION('',(-1.,0.,0.));
#747=VECTOR('',#746,1.);
#748=CARTESIAN_POINT('',(-57.2074120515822,0.,-43.7327831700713));
#749=LINE('',#748,#747);
#750=CARTESIAN_POINT('',(52.2074120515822,0.,-43.7327831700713));
#751=VERTEX_POINT('',#750);
#752=CARTESIAN_POINT('',(-52.2074120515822,0.,-43.7327831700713));
#753=VERTEX_POINT('',#752);
#754=EDGE_CURVE('E652',#751,#753,#749,.T.);
#755=ORIENTED_EDGE('',*,*,#754,.T.);
#756=DIRECTION('',(0.,-1.,0.));
#757=VECTOR('',#756,1.);
#758=CARTESIAN_POINT('',(-52.2074120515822,35.,-43.7327831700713));
#759=LINE('',#758,#757);
#760=CARTESIAN_POINT('',(-52.2074120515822,30.,-43.7327831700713));
#761=VERTEX_POINT('',#760);
#762=EDGE_CURVE('E669',#753,#761,#759,.F.);
#763=ORIENTED_EDGE('',*,*,#762,.T.);
#764=DIRECTION('',(-1.,0.,0.));
#765=VECTOR('',#764,1.);
#766=CARTESIAN_POINT('',(57.2074120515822,30.,-43.7327831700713));
#767=LINE('',#766,#765);
#768=CARTESIAN_POINT('',(52.2074120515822,30.,-43.7327831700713));
#769=VERTEX_POINT('',#768);
#770=EDGE_CURVE('E666',#761,#769,#767,.F.);
#771=ORIENTED_EDGE('',*,*,#770,.T.);
#772=DIRECTION('',(0.,-1.,0.));
#773=VECTOR('',#772,1.);
#774=CARTESIAN_POINT('',(52.2074120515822,35.,-43.7327831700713));
#775=LINE('',#774,#773);
#776=EDGE_CURVE('E664',#769,#751,#775,.T.);
#777=ORIENTED_EDGE('',*,*,#776,.T.);
#778=EDGE_LOOP('',(#755,#763,#771,#777));
#779=FACE_BOUND('',#778,.T.);
#780=ADVANCED_FACE('F818',(#779),#745,.F.);
#781=CARTESIAN_POINT('',(-57.2074120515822,0.,43.7327831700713));
#782=DIRECTION('',(0.,1.,0.));
#783=DIRECTION('',(0.,0.,1.));
#784=AXIS2_PLACEMENT_3D('',#781,#782,#783);
#785=PLANE('',#784);
#786=DIRECTION('',(1.,0.,0.));
#787=VECTOR('',#786,1.);
#788=CARTESIAN_POINT('',(-57.2074120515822,0.,40.7327831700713));
#789=LINE('',#788,#787);
#790=CARTESIAN_POINT('',(-52.2074120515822,0.,40.7327831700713));
#791=VERTEX_POINT('',#790);
#792=CARTESIAN_POINT('',(-40.6196419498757,0.,40.7327831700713));
#793=VERTEX_POINT('',#792);
#794=EDGE_CURVE('E603',#791,#793,#789,.T.);
#795=ORIENTED_EDGE('',*,*,#794,.T.);
#796=DIRECTION('',(0.,0.,1.));
#797=VECTOR('',#796,1.);
#798=CARTESIAN_POINT('',(-40.6196419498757,0.,-43.7337831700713));
#799=LINE('',#798,#797);
#800=EDGE_CURVE('E500',#793,#685,#799,.T.);
#801=ORIENTED_EDGE('',*,*,#800,.T.);
#802=ORIENTED_EDGE('',*,*,#686,.F.);
#803=CARTESIAN_POINT('',(-52.2074120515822,0.,38.7327831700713));
#804=DIRECTION('',(0.,1.,0.));
#805=DIRECTION('',(0.,0.,1.));
#806=AXIS2_PLACEMENT_3D('',#803,#804,#805);
#807=CIRCLE('',#806,5.);
#808=EDGE_CURVE('E691',#683,#661,#807,.F.);
#809=ORIENTED_EDGE('',*,*,#808,.T.);
#810=ORIENTED_EDGE('',*,*,#662,.F.);
#811=CARTESIAN_POINT('',(-52.2074120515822,0.,-38.7327831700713));
#812=DIRECTION('',(0.,1.,0.));
#813=DIRECTION('',(0.,0.,1.));
#814=AXIS2_PLACEMENT_3D('',#811,#812,#813);
#815=CIRCLE('',#814,5.);
#816=EDGE_CURVE('E698',#653,#753,#815,.F.);
#817=ORIENTED_EDGE('',*,*,#816,.T.);
#818=ORIENTED_EDGE('',*,*,#754,.F.);
#819=CARTESIAN_POINT('',(52.2074120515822,0.,-38.7327831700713));
#820=DIRECTION('',(0.,1.,0.));
#821=DIRECTION('',(0.,0.,1.));
#822=AXIS2_PLACEMENT_3D('',#819,#820,#821);
#823=CIRCLE('',#822,5.);
#824=EDGE_CURVE('E696',#751,#291,#823,.F.);
#825=ORIENTED_EDGE('',*,*,#824,.T.);
#826=ORIENTED_EDGE('',*,*,#292,.F.);
#827=CARTESIAN_POINT('',(52.2074120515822,0.,38.7327831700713));
#828=DIRECTION('',(0.,1.,0.));
#829=DIRECTION('',(0.,0.,1.));
#830=AXIS2_PLACEMENT_3D('',#827,#828,#829);
#831=CIRCLE('',#830,5.);
#832=EDGE_CURVE('E693',#283,#713,#831,.F.);
#833=ORIENTED_EDGE('',*,*,#832,.T.);
#834=ORIENTED_EDGE('',*,*,#714,.F.);
#835=DIRECTION('',(0.,0.,1.));
#836=VECTOR('',#835,1.);
#837=CARTESIAN_POINT('',(40.6196419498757,0.,-43.7337831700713));
#838=LINE('',#837,#836);
#839=CARTESIAN_POINT('',(40.6196419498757,0.,40.7327831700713));
#840=VERTEX_POINT('',#839);
#841=EDGE_CURVE('E497',#840,#709,#838,.T.);
#842=ORIENTED_EDGE('',*,*,#841,.F.);
#843=CARTESIAN_POINT('',(52.2074120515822,0.,40.7327831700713));
#844=VERTEX_POINT('',#843);
#845=EDGE_CURVE('E591',#840,#844,#789,.T.);
#846=ORIENTED_EDGE('',*,*,#845,.T.);
#847=CARTESIAN_POINT('',(52.2074120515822,0.,38.7327831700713));
#848=DIRECTION('',(0.,1.,0.));
#849=DIRECTION('',(0.,0.,1.));
#850=AXIS2_PLACEMENT_3D('',#847,#848,#849);
#851=CIRCLE('',#850,2.);
#852=EDGE_CURVE('E600',#480,#844,#851,.F.);
#853=ORIENTED_EDGE('',*,*,#852,.F.);
#854=ORIENTED_EDGE('',*,*,#481,.T.);
#855=CARTESIAN_POINT('',(52.2074120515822,0.,-38.7327831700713));
#856=DIRECTION('',(0.,1.,0.));
#857=DIRECTION('',(0.,0.,1.));
#858=AXIS2_PLACEMENT_3D('',#855,#856,#857);
#859=CIRCLE('',#858,2.);
#860=CARTESIAN_POINT('',(52.2074120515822,0.,-40.7327831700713));
#861=VERTEX_POINT('',#860);
#862=EDGE_CURVE('E595',#861,#472,#859,.F.);
#863=ORIENTED_EDGE('',*,*,#862,.F.);
#864=DIRECTION('',(-1.,0.,0.));
#865=VECTOR('',#864,1.);
#866=CARTESIAN_POINT('',(-57.2074120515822,0.,-40.7327831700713));
#867=LINE('',#866,#865);
#868=CARTESIAN_POINT('',(-52.2074120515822,0.,-40.7327831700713));
#869=VERTEX_POINT('',#868);
#870=EDGE_CURVE('E563',#861,#869,#867,.T.);
#871=ORIENTED_EDGE('',*,*,#870,.T.);
#872=CARTESIAN_POINT('',(-52.2074120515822,0.,-38.7327831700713));
#873=DIRECTION('',(0.,1.,0.));
#874=DIRECTION('',(0.,0.,1.));
#875=AXIS2_PLACEMENT_3D('',#872,#873,#874);
#876=CIRCLE('',#875,2.);
#877=CARTESIAN_POINT('',(-54.2074120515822,0.,-38.7327831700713));
#878=VERTEX_POINT('',#877);
#879=EDGE_CURVE('E592',#878,#869,#876,.F.);
#880=ORIENTED_EDGE('',*,*,#879,.F.);
#881=DIRECTION('',(0.,0.,1.));
#882=VECTOR('',#881,1.);
#883=CARTESIAN_POINT('',(-54.2074120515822,0.,-43.7327831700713));
#884=LINE('',#883,#882);
#885=CARTESIAN_POINT('',(-54.2074120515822,0.,38.7327831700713));
#886=VERTEX_POINT('',#885);
#887=EDGE_CURVE('E541',#878,#886,#884,.T.);
#888=ORIENTED_EDGE('',*,*,#887,.T.);
#889=CARTESIAN_POINT('',(-52.2074120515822,0.,38.7327831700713));
#890=DIRECTION('',(0.,1.,0.));
#891=DIRECTION('',(0.,0.,1.));
#892=AXIS2_PLACEMENT_3D('',#889,#890,#891);
#893=CIRCLE('',#892,2.);
#894=EDGE_CURVE('E519',#791,#886,#893,.F.);
#895=ORIENTED_EDGE('',*,*,#894,.F.);
#896=EDGE_LOOP('',(#795,#801,#802,#809,#810,#817,#818,#825,#826,#833,#834,#842,#846,#853,#854,
#863,#871,#880,#888,#895));
#897=FACE_BOUND('',#896,.T.);
#898=ADVANCED_FACE('F815',(#897),#785,.F.);
#899=CARTESIAN_POINT('',(52.2074120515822,35.,38.7327831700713));
#900=DIRECTION('',(0.,-1.,0.));
#901=DIRECTION('',(0.,0.,-1.));
#902=AXIS2_PLACEMENT_3D('',#899,#900,#901);
#903=CYLINDRICAL_SURFACE('',#902,5.);
#904=ORIENTED_EDGE('',*,*,#832,.F.);
#905=ORIENTED_EDGE('',*,*,#284,.F.);
#906=CARTESIAN_POINT('',(52.2074120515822,30.,38.7327831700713));
#907=DIRECTION('',(0.,1.,0.));
#908=DIRECTION('',(0.,0.,1.));
#909=AXIS2_PLACEMENT_3D('',#906,#907,#908);
#910=CIRCLE('',#909,5.);
#911=EDGE_CURVE('E639',#721,#275,#910,.T.);
#912=ORIENTED_EDGE('',*,*,#911,.F.);
#913=ORIENTED_EDGE('',*,*,#722,.F.);
#914=EDGE_LOOP('',(#904,#905,#912,#913));
#915=FACE_BOUND('',#914,.T.);
#916=ADVANCED_FACE('F830',(#915),#903,.T.);
#917=CARTESIAN_POINT('',(-57.2074120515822,30.,38.7327831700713));
#918=DIRECTION('',(-1.,0.,0.));
#919=DIRECTION('',(0.,0.,1.));
#920=AXIS2_PLACEMENT_3D('',#917,#918,#919);
#921=CYLINDRICAL_SURFACE('',#920,5.);
#922=CARTESIAN_POINT('',(-52.2074120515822,30.,38.7327831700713));
#923=DIRECTION('',(-1.,0.,0.));
#924=DIRECTION('',(0.,0.,1.));
#925=AXIS2_PLACEMENT_3D('',#922,#923,#924);
#926=CIRCLE('',#925,5.);
#927=EDGE_CURVE('E633',#729,#352,#926,.T.);
#928=ORIENTED_EDGE('',*,*,#927,.F.);
#929=ORIENTED_EDGE('',*,*,#730,.F.);
#930=CARTESIAN_POINT('',(52.2074120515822,30.,38.7327831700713));
#931=DIRECTION('',(1.,0.,0.));
#932=DIRECTION('',(0.,0.,-1.));
#933=AXIS2_PLACEMENT_3D('',#930,#931,#932);
#934=CIRCLE('',#933,5.);
#935=EDGE_CURVE('E636',#360,#721,#934,.T.);
#936=ORIENTED_EDGE('',*,*,#935,.F.);
#937=ORIENTED_EDGE('',*,*,#361,.F.);
#938=EDGE_LOOP('',(#928,#929,#936,#937));
#939=FACE_BOUND('',#938,.T.);
#940=ADVANCED_FACE('F795',(#939),#921,.T.);
#941=CARTESIAN_POINT('',(-52.2074120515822,35.,38.7327831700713));
#942=DIRECTION('',(0.,-1.,0.));
#943=DIRECTION('',(0.,0.,-1.));
#944=AXIS2_PLACEMENT_3D('',#941,#942,#943);
#945=CYLINDRICAL_SURFACE('',#944,5.);
#946=ORIENTED_EDGE('',*,*,#808,.F.);
#947=ORIENTED_EDGE('',*,*,#736,.F.);
#948=CARTESIAN_POINT('',(-52.2074120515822,30.,38.7327831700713));
#949=DIRECTION('',(0.,1.,0.));
#950=DIRECTION('',(0.,0.,1.));
#951=AXIS2_PLACEMENT_3D('',#948,#949,#950);
#952=CIRCLE('',#951,5.);
#953=EDGE_CURVE('E630',#643,#729,#952,.T.);
#954=ORIENTED_EDGE('',*,*,#953,.F.);
#955=ORIENTED_EDGE('',*,*,#668,.F.);
#956=EDGE_LOOP('',(#946,#947,#954,#955));
#957=FACE_BOUND('',#956,.T.);
#958=ADVANCED_FACE('F865',(#957),#945,.T.);
#959=CARTESIAN_POINT('',(52.2074120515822,30.,38.7327831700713));
#960=DIRECTION('',(0.,0.,1.));
#961=DIRECTION('',(1.,0.,0.));
#962=AXIS2_PLACEMENT_3D('',#959,#960,#961);
#963=SPHERICAL_SURFACE('',#962,5.);
#964=ORIENTED_EDGE('',*,*,#935,.T.);
#965=ORIENTED_EDGE('',*,*,#911,.T.);
#966=ORIENTED_EDGE('',*,*,#431,.F.);
#967=EDGE_LOOP('',(#964,#965,#966));
#968=FACE_BOUND('',#967,.T.);
#969=ADVANCED_FACE('F833',(#968),#963,.T.);
#970=CARTESIAN_POINT('',(-52.2074120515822,30.,38.7327831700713));
#971=DIRECTION('',(0.,0.,1.));
#972=DIRECTION('',(1.,0.,0.));
#973=AXIS2_PLACEMENT_3D('',#970,#971,#972);
#974=SPHERICAL_SURFACE('',#973,5.);
#975=ORIENTED_EDGE('',*,*,#953,.T.);
#976=ORIENTED_EDGE('',*,*,#927,.T.);
#977=CARTESIAN_POINT('',(-52.2074120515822,30.,38.7327831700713));
#978=DIRECTION('',(0.,0.,1.));
#979=DIRECTION('',(1.,0.,0.));
#980=AXIS2_PLACEMENT_3D('',#977,#978,#979);
#981=CIRCLE('',#980,5.);
#982=EDGE_CURVE('E624',#643,#352,#981,.F.);
#983=ORIENTED_EDGE('',*,*,#982,.F.);
#984=EDGE_LOOP('',(#975,#976,#983));
#985=FACE_BOUND('',#984,.T.);
#986=ADVANCED_FACE('F800',(#985),#974,.T.);
#987=CARTESIAN_POINT('',(52.2074120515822,35.,-38.7327831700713));
#988=DIRECTION('',(0.,-1.,0.));
#989=DIRECTION('',(0.,0.,-1.));
#990=AXIS2_PLACEMENT_3D('',#987,#988,#989);
#991=CYLINDRICAL_SURFACE('',#990,5.);
#992=ORIENTED_EDGE('',*,*,#824,.F.);
#993=ORIENTED_EDGE('',*,*,#776,.F.);
#994=CARTESIAN_POINT('',(52.2074120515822,30.,-38.7327831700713));
#995=DIRECTION('',(0.,1.,0.));
#996=DIRECTION('',(0.,0.,1.));
#997=AXIS2_PLACEMENT_3D('',#994,#995,#996);
#998=CIRCLE('',#997,5.);
#999=EDGE_CURVE('E621',#299,#769,#998,.T.);
#1000=ORIENTED_EDGE('',*,*,#999,.F.);
#1001=ORIENTED_EDGE('',*,*,#300,.F.);
#1002=EDGE_LOOP('',(#992,#993,#1000,#1001));
#1003=FACE_BOUND('',#1002,.T.);
#1004=ADVANCED_FACE('F820',(#1003),#991,.T.);
#1005=CARTESIAN_POINT('',(-52.2074120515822,30.,43.7327831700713));
#1006=DIRECTION('',(0.,0.,-1.));
#1007=DIRECTION('',(-1.,0.,0.));
#1008=AXIS2_PLACEMENT_3D('',#1005,#1006,#1007);
#1009=CYLINDRICAL_SURFACE('',#1008,5.);
#1010=ORIENTED_EDGE('',*,*,#982,.T.);
#1011=ORIENTED_EDGE('',*,*,#353,.F.);
#1012=CARTESIAN_POINT('',(-52.2074120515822,30.,-38.7327831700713));
#1013=DIRECTION('',(0.,0.,-1.));
#1014=DIRECTION('',(-1.,0.,0.));
#1015=AXIS2_PLACEMENT_3D('',#1012,#1013,#1014);
#1016=CIRCLE('',#1015,5.);
#1017=EDGE_CURVE('E615',#645,#344,#1016,.T.);
#1018=ORIENTED_EDGE('',*,*,#1017,.F.);
#1019=ORIENTED_EDGE('',*,*,#646,.F.);
#1020=EDGE_LOOP('',(#1010,#1011,#1018,#1019));
#1021=FACE_BOUND('',#1020,.T.);
#1022=ADVANCED_FACE('F803',(#1021),#1009,.T.);
#1023=CARTESIAN_POINT('',(-52.2074120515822,35.,-38.7327831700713));
#1024=DIRECTION('',(0.,-1.,0.));
#1025=DIRECTION('',(0.,0.,-1.));
#1026=AXIS2_PLACEMENT_3D('',#1023,#1024,#1025);
#1027=CYLINDRICAL_SURFACE('',#1026,5.);
#1028=ORIENTED_EDGE('',*,*,#816,.F.);
#1029=ORIENTED_EDGE('',*,*,#654,.F.);
#1030=CARTESIAN_POINT('',(-52.2074120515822,30.,-38.7327831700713));
#1031=DIRECTION('',(0.,1.,0.));
#1032=DIRECTION('',(0.,0.,1.));
#1033=AXIS2_PLACEMENT_3D('',#1030,#1031,#1032);
#1034=CIRCLE('',#1033,5.);
#1035=EDGE_CURVE('E612',#761,#645,#1034,.T.);
#1036=ORIENTED_EDGE('',*,*,#1035,.F.);
#1037=ORIENTED_EDGE('',*,*,#762,.F.);
#1038=EDGE_LOOP('',(#1028,#1029,#1036,#1037));
#1039=FACE_BOUND('',#1038,.T.);
#1040=ADVANCED_FACE('F811',(#1039),#1027,.T.);
#1041=CARTESIAN_POINT('',(52.2074120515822,30.,-38.7327831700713));
#1042=DIRECTION('',(0.,0.,1.));
#1043=DIRECTION('',(1.,0.,0.));
#1044=AXIS2_PLACEMENT_3D('',#1041,#1042,#1043);
#1045=SPHERICAL_SURFACE('',#1044,5.);
#1046=ORIENTED_EDGE('',*,*,#412,.T.);
#1047=ORIENTED_EDGE('',*,*,#999,.T.);
#1048=CARTESIAN_POINT('',(52.2074120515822,30.,-38.7327831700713));
#1049=DIRECTION('',(1.,0.,0.));
#1050=DIRECTION('',(0.,1.,0.));
#1051=AXIS2_PLACEMENT_3D('',#1048,#1049,#1050);
#1052=CIRCLE('',#1051,5.);
#1053=EDGE_CURVE('E610',#336,#769,#1052,.F.);
#1054=ORIENTED_EDGE('',*,*,#1053,.F.);
#1055=EDGE_LOOP('',(#1046,#1047,#1054));
#1056=FACE_BOUND('',#1055,.T.);
#1057=ADVANCED_FACE('F782',(#1056),#1045,.T.);
#1058=CARTESIAN_POINT('',(-52.2074120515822,30.,-38.7327831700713));
#1059=DIRECTION('',(0.,0.,1.));
#1060=DIRECTION('',(1.,0.,0.));
#1061=AXIS2_PLACEMENT_3D('',#1058,#1059,#1060);
#1062=SPHERICAL_SURFACE('',#1061,5.);
#1063=ORIENTED_EDGE('',*,*,#1035,.T.);
#1064=ORIENTED_EDGE('',*,*,#1017,.T.);
#1065=CARTESIAN_POINT('',(-52.2074120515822,30.,-38.7327831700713));
#1066=DIRECTION('',(-1.,0.,0.));
#1067=DIRECTION('',(0.,0.,1.));
#1068=AXIS2_PLACEMENT_3D('',#1065,#1066,#1067);
#1069=CIRCLE('',#1068,5.);
#1070=EDGE_CURVE('E594',#761,#344,#1069,.F.);
#1071=ORIENTED_EDGE('',*,*,#1070,.F.);
#1072=EDGE_LOOP('',(#1063,#1064,#1071));
#1073=FACE_BOUND('',#1072,.T.);
#1074=ADVANCED_FACE('F940',(#1073),#1062,.T.);
#1075=CARTESIAN_POINT('',(-57.2074120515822,30.,-38.7327831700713));
#1076=DIRECTION('',(1.,0.,0.));
#1077=DIRECTION('',(0.,0.,-1.));
#1078=AXIS2_PLACEMENT_3D('',#1075,#1076,#1077);
#1079=CYLINDRICAL_SURFACE('',#1078,5.);
#1080=ORIENTED_EDGE('',*,*,#1053,.T.);
#1081=ORIENTED_EDGE('',*,*,#770,.F.);
#1082=ORIENTED_EDGE('',*,*,#1070,.T.);
#1083=ORIENTED_EDGE('',*,*,#345,.F.);
#1084=EDGE_LOOP('',(#1080,#1081,#1082,#1083));
#1085=FACE_BOUND('',#1084,.T.);
#1086=ADVANCED_FACE('F786',(#1085),#1079,.T.);
#1087=CARTESIAN_POINT('',(-54.2074120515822,35.,-43.7327831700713));
#1088=DIRECTION('',(1.,0.,0.));
#1089=DIRECTION('',(0.,0.,-1.));
#1090=AXIS2_PLACEMENT_3D('',#1087,#1088,#1089);
#1091=PLANE('',#1090);
#1092=DIRECTION('',(0.,0.,-1.));
#1093=VECTOR('',#1092,1.);
#1094=CARTESIAN_POINT('',(-54.2074120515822,30.,-43.7327831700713));
#1095=LINE('',#1094,#1093);
#1096=CARTESIAN_POINT('',(-54.2074120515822,30.,38.7327831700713));
#1097=VERTEX_POINT('',#1096);
#1098=CARTESIAN_POINT('',(-54.2074120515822,30.,-38.7327831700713));
#1099=VERTEX_POINT('',#1098);
#1100=EDGE_CURVE('E514',#1097,#1099,#1095,.T.);
#1101=ORIENTED_EDGE('',*,*,#1100,.F.);
#1102=DIRECTION('',(0.,1.,0.));
#1103=VECTOR('',#1102,1.);
#1104=CARTESIAN_POINT('',(-54.2074120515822,35.,38.7327831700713));
#1105=LINE('',#1104,#1103);
#1106=EDGE_CURVE('E517',#886,#1097,#1105,.T.);
#1107=ORIENTED_EDGE('',*,*,#1106,.F.);
#1108=ORIENTED_EDGE('',*,*,#887,.F.);
#1109=DIRECTION('',(0.,1.,0.));
#1110=VECTOR('',#1109,1.);
#1111=CARTESIAN_POINT('',(-54.2074120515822,35.,-38.7327831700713));
#1112=LINE('',#1111,#1110);
#1113=EDGE_CURVE('E516',#1099,#878,#1112,.F.);
#1114=ORIENTED_EDGE('',*,*,#1113,.F.);
#1115=EDGE_LOOP('',(#1101,#1107,#1108,#1114));
#1116=FACE_BOUND('',#1115,.T.);
#1117=ADVANCED_FACE('F958',(#1116),#1091,.T.);
#1118=CARTESIAN_POINT('',(-57.2074120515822,35.,40.7327831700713));
#1119=DIRECTION('',(0.,0.,-1.));
#1120=DIRECTION('',(-1.,0.,0.));
#1121=AXIS2_PLACEMENT_3D('',#1118,#1119,#1120);
#1122=PLANE('',#1121);
#1123=DIRECTION('',(0.,-1.,0.));
#1124=VECTOR('',#1123,1.);
#1125=CARTESIAN_POINT('',(-40.6196419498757,0.,40.7327831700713));
#1126=LINE('',#1125,#1124);
#1127=CARTESIAN_POINT('',(-40.6196419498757,13.7609534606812,40.7327831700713));
#1128=VERTEX_POINT('',#1127);
#1129=EDGE_CURVE('E487',#1128,#793,#1126,.T.);
#1130=ORIENTED_EDGE('',*,*,#1129,.T.);
#1131=ORIENTED_EDGE('',*,*,#794,.F.);
#1132=DIRECTION('',(0.,1.,0.));
#1133=VECTOR('',#1132,1.);
#1134=CARTESIAN_POINT('',(-52.2074120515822,35.,40.7327831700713));
#1135=LINE('',#1134,#1133);
#1136=CARTESIAN_POINT('',(-52.2074120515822,30.,40.7327831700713));
#1137=VERTEX_POINT('',#1136);
#1138=EDGE_CURVE('E522',#1137,#791,#1135,.F.);
#1139=ORIENTED_EDGE('',*,*,#1138,.F.);
#1140=DIRECTION('',(-1.,0.,0.));
#1141=VECTOR('',#1140,1.);
#1142=CARTESIAN_POINT('',(-57.2074120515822,30.,40.7327831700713));
#1143=LINE('',#1142,#1141);
#1144=CARTESIAN_POINT('',(52.2074120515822,30.,40.7327831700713));
#1145=VERTEX_POINT('',#1144);
#1146=EDGE_CURVE('E525',#1145,#1137,#1143,.T.);
#1147=ORIENTED_EDGE('',*,*,#1146,.F.);
#1148=DIRECTION('',(0.,1.,0.));
#1149=VECTOR('',#1148,1.);
#1150=CARTESIAN_POINT('',(52.2074120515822,35.,40.7327831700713));
#1151=LINE('',#1150,#1149);
#1152=EDGE_CURVE('E521',#844,#1145,#1151,.T.);
#1153=ORIENTED_EDGE('',*,*,#1152,.F.);
#1154=ORIENTED_EDGE('',*,*,#845,.F.);
#1155=DIRECTION('',(0.,1.,0.));
#1156=VECTOR('',#1155,1.);
#1157=CARTESIAN_POINT('',(40.6196419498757,0.,40.7327831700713));
#1158=LINE('',#1157,#1156);
#1159=CARTESIAN_POINT('',(40.6196419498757,13.7609534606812,40.7327831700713));
#1160=VERTEX_POINT('',#1159);
#1161=EDGE_CURVE('E505',#840,#1160,#1158,.T.);
#1162=ORIENTED_EDGE('',*,*,#1161,.T.);
#1163=DIRECTION('',(-1.,0.,0.));
#1164=VECTOR('',#1163,1.);
#1165=CARTESIAN_POINT('',(-40.6196419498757,13.7609534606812,40.7327831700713));
#1166=LINE('',#1165,#1164);
#1167=EDGE_CURVE('E501',#1160,#1128,#1166,.T.);
#1168=ORIENTED_EDGE('',*,*,#1167,.T.);
#1169=EDGE_LOOP('',(#1130,#1131,#1139,#1147,#1153,#1154,#1162,#1168));
#1170=FACE_BOUND('',#1169,.T.);
#1171=ADVANCED_FACE('F967',(#1170),#1122,.T.);
#1172=CARTESIAN_POINT('',(-57.2074120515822,35.,-40.7327831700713));
#1173=DIRECTION('',(0.,0.,1.));
#1174=DIRECTION('',(1.,0.,0.));
#1175=AXIS2_PLACEMENT_3D('',#1172,#1173,#1174);
#1176=PLANE('',#1175);
#1177=ORIENTED_EDGE('',*,*,#870,.F.);
#1178=DIRECTION('',(0.,1.,0.));
#1179=VECTOR('',#1178,1.);
#1180=CARTESIAN_POINT('',(52.2074120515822,35.,-40.7327831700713));
#1181=LINE('',#1180,#1179);
#1182=CARTESIAN_POINT('',(52.2074120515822,30.,-40.7327831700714));
#1183=VERTEX_POINT('',#1182);
#1184=EDGE_CURVE('E559',#1183,#861,#1181,.F.);
#1185=ORIENTED_EDGE('',*,*,#1184,.F.);
#1186=DIRECTION('',(1.,0.,0.));
#1187=VECTOR('',#1186,1.);
#1188=CARTESIAN_POINT('',(-57.2074120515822,30.,-40.7327831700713));
#1189=LINE('',#1188,#1187);
#1190=CARTESIAN_POINT('',(-52.2074120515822,30.,-40.7327831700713));
#1191=VERTEX_POINT('',#1190);
#1192=EDGE_CURVE('E579',#1191,#1183,#1189,.T.);
#1193=ORIENTED_EDGE('',*,*,#1192,.F.);
#1194=DIRECTION('',(0.,1.,0.));
#1195=VECTOR('',#1194,1.);
#1196=CARTESIAN_POINT('',(-52.2074120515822,35.,-40.7327831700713));
#1197=LINE('',#1196,#1195);
#1198=EDGE_CURVE('E537',#869,#1191,#1197,.T.);
#1199=ORIENTED_EDGE('',*,*,#1198,.F.);
#1200=EDGE_LOOP('',(#1177,#1185,#1193,#1199));
#1201=FACE_BOUND('',#1200,.T.);
#1202=ADVANCED_FACE('F742',(#1201),#1176,.T.);
#1203=CARTESIAN_POINT('',(52.2074120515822,35.,38.7327831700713));
#1204=DIRECTION('',(0.,-1.,0.));
#1205=DIRECTION('',(0.,0.,-1.));
#1206=AXIS2_PLACEMENT_3D('',#1203,#1204,#1205);
#1207=CYLINDRICAL_SURFACE('',#1206,2.);
#1208=ORIENTED_EDGE('',*,*,#852,.T.);
#1209=ORIENTED_EDGE('',*,*,#1152,.T.);
#1210=CARTESIAN_POINT('',(52.2074120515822,30.,38.7327831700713));
#1211=DIRECTION('',(0.,-1.,0.));
#1212=DIRECTION('',(0.,0.,-1.));
#1213=AXIS2_PLACEMENT_3D('',#1210,#1211,#1212);
#1214=CIRCLE('',#1213,2.);
#1215=EDGE_CURVE('E538',#1145,#488,#1214,.F.);
#1216=ORIENTED_EDGE('',*,*,#1215,.T.);
#1217=ORIENTED_EDGE('',*,*,#489,.T.);
#1218=EDGE_LOOP('',(#1208,#1209,#1216,#1217));
#1219=FACE_BOUND('',#1218,.T.);
#1220=ADVANCED_FACE('F979',(#1219),#1207,.F.);
#1221=CARTESIAN_POINT('',(-57.2074120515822,30.,38.7327831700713));
#1222=DIRECTION('',(-1.,0.,0.));
#1223=DIRECTION('',(0.,0.,1.));
#1224=AXIS2_PLACEMENT_3D('',#1221,#1222,#1223);
#1225=CYLINDRICAL_SURFACE('',#1224,2.);
#1226=CARTESIAN_POINT('',(-52.2074120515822,30.,38.7327831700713));
#1227=DIRECTION('',(1.,0.,0.));
#1228=DIRECTION('',(0.,1.,0.));
#1229=AXIS2_PLACEMENT_3D('',#1226,#1227,#1228);
#1230=CIRCLE('',#1229,2.);
#1231=EDGE_CURVE('E530',#1137,#566,#1230,.F.);
#1232=ORIENTED_EDGE('',*,*,#1231,.T.);
#1233=ORIENTED_EDGE('',*,*,#567,.T.);
#1234=CARTESIAN_POINT('',(52.2074120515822,30.,38.7327831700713));
#1235=DIRECTION('',(1.,0.,0.));
#1236=DIRECTION('',(0.,1.,0.));
#1237=AXIS2_PLACEMENT_3D('',#1234,#1235,#1236);
#1238=CIRCLE('',#1237,2.);
#1239=EDGE_CURVE('E542',#558,#1145,#1238,.T.);
#1240=ORIENTED_EDGE('',*,*,#1239,.T.);
#1241=ORIENTED_EDGE('',*,*,#1146,.T.);
#1242=EDGE_LOOP('',(#1232,#1233,#1240,#1241));
#1243=FACE_BOUND('',#1242,.T.);
#1244=ADVANCED_FACE('F988',(#1243),#1225,.F.);
#1245=CARTESIAN_POINT('',(-52.2074120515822,35.,38.7327831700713));
#1246=DIRECTION('',(0.,-1.,0.));
#1247=DIRECTION('',(0.,0.,-1.));
#1248=AXIS2_PLACEMENT_3D('',#1245,#1246,#1247);
#1249=CYLINDRICAL_SURFACE('',#1248,2.);
#1250=ORIENTED_EDGE('',*,*,#894,.T.);
#1251=ORIENTED_EDGE('',*,*,#1106,.T.);
#1252=CARTESIAN_POINT('',(-52.2074120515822,30.,38.7327831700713));
#1253=DIRECTION('',(0.,1.,0.));
#1254=DIRECTION('',(-1.,0.,0.));
#1255=AXIS2_PLACEMENT_3D('',#1252,#1253,#1254);
#1256=CIRCLE('',#1255,2.);
#1257=EDGE_CURVE('E527',#1097,#1137,#1256,.T.);
#1258=ORIENTED_EDGE('',*,*,#1257,.T.);
#1259=ORIENTED_EDGE('',*,*,#1138,.T.);
#1260=EDGE_LOOP('',(#1250,#1251,#1258,#1259));
#1261=FACE_BOUND('',#1260,.T.);
#1262=ADVANCED_FACE('F998',(#1261),#1249,.F.);
#1263=CARTESIAN_POINT('',(52.2074120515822,30.,38.7327831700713));
#1264=DIRECTION('',(0.,0.,1.));
#1265=DIRECTION('',(1.,0.,0.));
#1266=AXIS2_PLACEMENT_3D('',#1263,#1264,#1265);
#1267=SPHERICAL_SURFACE('',#1266,2.);
#1268=ORIENTED_EDGE('',*,*,#1239,.F.);
#1269=ORIENTED_EDGE('',*,*,#627,.T.);
#1270=ORIENTED_EDGE('',*,*,#1215,.F.);
#1271=EDGE_LOOP('',(#1268,#1269,#1270));
#1272=FACE_BOUND('',#1271,.T.);
#1273=ADVANCED_FACE('F1008',(#1272),#1267,.F.);
#1274=CARTESIAN_POINT('',(-52.2074120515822,30.,38.7327831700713));
#1275=DIRECTION('',(0.,0.,1.));
#1276=DIRECTION('',(1.,0.,0.));
#1277=AXIS2_PLACEMENT_3D('',#1274,#1275,#1276);
#1278=SPHERICAL_SURFACE('',#1277,2.);
#1279=ORIENTED_EDGE('',*,*,#1257,.F.);
#1280=CARTESIAN_POINT('',(-52.2074120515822,30.,38.7327831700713));
#1281=DIRECTION('',(0.,0.,-1.));
#1282=DIRECTION('',(-1.,0.,0.));
#1283=AXIS2_PLACEMENT_3D('',#1280,#1281,#1282);
#1284=CIRCLE('',#1283,2.);
#1285=EDGE_CURVE('E551',#1097,#566,#1284,.T.);
#1286=ORIENTED_EDGE('',*,*,#1285,.T.);
#1287=ORIENTED_EDGE('',*,*,#1231,.F.);
#1288=EDGE_LOOP('',(#1279,#1286,#1287));
#1289=FACE_BOUND('',#1288,.T.);
#1290=ADVANCED_FACE('F1018',(#1289),#1278,.F.);
#1291=CARTESIAN_POINT('',(52.2074120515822,35.,-38.7327831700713));
#1292=DIRECTION('',(0.,-1.,0.));
#1293=DIRECTION('',(0.,0.,-1.));
#1294=AXIS2_PLACEMENT_3D('',#1291,#1292,#1293);
#1295=CYLINDRICAL_SURFACE('',#1294,2.);
#1296=ORIENTED_EDGE('',*,*,#862,.T.);
#1297=ORIENTED_EDGE('',*,*,#473,.T.);
#1298=CARTESIAN_POINT('',(52.2074120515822,30.,-38.7327831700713));
#1299=DIRECTION('',(0.,-1.,0.));
#1300=DIRECTION('',(0.,0.,-1.));
#1301=AXIS2_PLACEMENT_3D('',#1298,#1299,#1300);
#1302=CIRCLE('',#1301,2.);
#1303=EDGE_CURVE('E569',#464,#1183,#1302,.F.);
#1304=ORIENTED_EDGE('',*,*,#1303,.T.);
#1305=ORIENTED_EDGE('',*,*,#1184,.T.);
#1306=EDGE_LOOP('',(#1296,#1297,#1304,#1305));
#1307=FACE_BOUND('',#1306,.T.);
#1308=ADVANCED_FACE('F745',(#1307),#1295,.F.);
#1309=CARTESIAN_POINT('',(-52.2074120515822,30.,43.7327831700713));
#1310=DIRECTION('',(0.,0.,-1.));
#1311=DIRECTION('',(-1.,0.,0.));
#1312=AXIS2_PLACEMENT_3D('',#1309,#1310,#1311);
#1313=CYLINDRICAL_SURFACE('',#1312,2.);
#1314=ORIENTED_EDGE('',*,*,#1285,.F.);
#1315=ORIENTED_EDGE('',*,*,#1100,.T.);
#1316=CARTESIAN_POINT('',(-52.2074120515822,30.,-38.7327831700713));
#1317=DIRECTION('',(0.,0.,1.));
#1318=DIRECTION('',(1.,0.,0.));
#1319=AXIS2_PLACEMENT_3D('',#1316,#1317,#1318);
#1320=CIRCLE('',#1319,2.);
#1321=EDGE_CURVE('E570',#1099,#574,#1320,.F.);
#1322=ORIENTED_EDGE('',*,*,#1321,.T.);
#1323=ORIENTED_EDGE('',*,*,#575,.T.);
#1324=EDGE_LOOP('',(#1314,#1315,#1322,#1323));
#1325=FACE_BOUND('',#1324,.T.);
#1326=ADVANCED_FACE('F1037',(#1325),#1313,.F.);
#1327=CARTESIAN_POINT('',(-52.2074120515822,35.,-38.7327831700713));
#1328=DIRECTION('',(0.,-1.,0.));
#1329=DIRECTION('',(0.,0.,-1.));
#1330=AXIS2_PLACEMENT_3D('',#1327,#1328,#1329);
#1331=CYLINDRICAL_SURFACE('',#1330,2.);
#1332=ORIENTED_EDGE('',*,*,#879,.T.);
#1333=ORIENTED_EDGE('',*,*,#1198,.T.);
#1334=CARTESIAN_POINT('',(-52.2074120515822,30.,-38.7327831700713));
#1335=DIRECTION('',(0.,1.,0.));
#1336=DIRECTION('',(-1.,0.,0.));
#1337=AXIS2_PLACEMENT_3D('',#1334,#1335,#1336);
#1338=CIRCLE('',#1337,2.);
#1339=EDGE_CURVE('E574',#1191,#1099,#1338,.T.);
#1340=ORIENTED_EDGE('',*,*,#1339,.T.);
#1341=ORIENTED_EDGE('',*,*,#1113,.T.);
#1342=EDGE_LOOP('',(#1332,#1333,#1340,#1341));
#1343=FACE_BOUND('',#1342,.T.);
#1344=ADVANCED_FACE('F1046',(#1343),#1331,.F.);
#1345=CARTESIAN_POINT('',(52.2074120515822,30.,-38.7327831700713));
#1346=DIRECTION('',(0.,0.,1.));
#1347=DIRECTION('',(1.,0.,0.));
#1348=AXIS2_PLACEMENT_3D('',#1345,#1346,#1347);
#1349=SPHERICAL_SURFACE('',#1348,2.);
#1350=ORIENTED_EDGE('',*,*,#608,.F.);
#1351=CARTESIAN_POINT('',(52.2074120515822,30.,-38.7327831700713));
#1352=DIRECTION('',(1.,0.,0.));
#1353=DIRECTION('',(0.,0.,-1.));
#1354=AXIS2_PLACEMENT_3D('',#1351,#1352,#1353);
#1355=CIRCLE('',#1354,2.);
#1356=EDGE_CURVE('E577',#582,#1183,#1355,.F.);
#1357=ORIENTED_EDGE('',*,*,#1356,.T.);
#1358=ORIENTED_EDGE('',*,*,#1303,.F.);
#1359=EDGE_LOOP('',(#1350,#1357,#1358));
#1360=FACE_BOUND('',#1359,.T.);
#1361=ADVANCED_FACE('F733',(#1360),#1349,.F.);
#1362=CARTESIAN_POINT('',(-52.2074120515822,30.,-38.7327831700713));
#1363=DIRECTION('',(0.,0.,1.));
#1364=DIRECTION('',(1.,0.,0.));
#1365=AXIS2_PLACEMENT_3D('',#1362,#1363,#1364);
#1366=SPHERICAL_SURFACE('',#1365,2.);
#1367=ORIENTED_EDGE('',*,*,#1339,.F.);
#1368=CARTESIAN_POINT('',(-52.2074120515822,30.,-38.7327831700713));
#1369=DIRECTION('',(1.,0.,0.));
#1370=DIRECTION('',(0.,0.,-1.));
#1371=AXIS2_PLACEMENT_3D('',#1368,#1369,#1370);
#1372=CIRCLE('',#1371,2.);
#1373=EDGE_CURVE('E491',#1191,#574,#1372,.T.);
#1374=ORIENTED_EDGE('',*,*,#1373,.T.);
#1375=ORIENTED_EDGE('',*,*,#1321,.F.);
#1376=EDGE_LOOP('',(#1367,#1374,#1375));
#1377=FACE_BOUND('',#1376,.T.);
#1378=ADVANCED_FACE('F1065',(#1377),#1366,.F.);
#1379=CARTESIAN_POINT('',(-57.2074120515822,30.,-38.7327831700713));
#1380=DIRECTION('',(1.,0.,0.));
#1381=DIRECTION('',(0.,0.,-1.));
#1382=AXIS2_PLACEMENT_3D('',#1379,#1380,#1381);
#1383=CYLINDRICAL_SURFACE('',#1382,2.);
#1384=ORIENTED_EDGE('',*,*,#1356,.F.);
#1385=ORIENTED_EDGE('',*,*,#583,.T.);
#1386=ORIENTED_EDGE('',*,*,#1373,.F.);
#1387=ORIENTED_EDGE('',*,*,#1192,.T.);
#1388=EDGE_LOOP('',(#1384,#1385,#1386,#1387));
#1389=FACE_BOUND('',#1388,.T.);
#1390=ADVANCED_FACE('F735',(#1389),#1383,.F.);
#1391=CARTESIAN_POINT('',(-40.6196419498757,0.,-43.7337831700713));
#1392=DIRECTION('',(-1.,0.,0.));
#1393=DIRECTION('',(0.,0.,1.));
#1394=AXIS2_PLACEMENT_3D('',#1391,#1392,#1393);
#1395=PLANE('',#1394);
#1396=DIRECTION('',(0.,0.,1.));
#1397=VECTOR('',#1396,1.);
#1398=CARTESIAN_POINT('',(-40.6196419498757,13.7609534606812,-43.7337831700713));
#1399=LINE('',#1398,#1397);
#1400=EDGE_CURVE('E504',#1128,#693,#1399,.T.);
#1401=ORIENTED_EDGE('',*,*,#1400,.T.);
#1402=ORIENTED_EDGE('',*,*,#694,.T.);
#1403=ORIENTED_EDGE('',*,*,#800,.F.);
#1404=ORIENTED_EDGE('',*,*,#1129,.F.);
#1405=EDGE_LOOP('',(#1401,#1402,#1403,#1404));
#1406=FACE_BOUND('',#1405,.T.);
#1407=ADVANCED_FACE('F1082',(#1406),#1395,.F.);
#1408=CARTESIAN_POINT('',(-40.6196419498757,13.7609534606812,-43.7337831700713));
#1409=DIRECTION('',(0.,1.,0.));
#1410=DIRECTION('',(0.,0.,1.));
#1411=AXIS2_PLACEMENT_3D('',#1408,#1409,#1410);
#1412=PLANE('',#1411);
#1413=DIRECTION('',(0.,0.,1.));
#1414=VECTOR('',#1413,1.);
#1415=CARTESIAN_POINT('',(40.6196419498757,13.7609534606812,-43.7337831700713));
#1416=LINE('',#1415,#1414);
#1417=EDGE_CURVE('E508',#1160,#701,#1416,.T.);
#1418=ORIENTED_EDGE('',*,*,#1417,.T.);
#1419=ORIENTED_EDGE('',*,*,#702,.T.);
#1420=ORIENTED_EDGE('',*,*,#1400,.F.);
#1421=ORIENTED_EDGE('',*,*,#1167,.F.);
#1422=EDGE_LOOP('',(#1418,#1419,#1420,#1421));
#1423=FACE_BOUND('',#1422,.T.);
#1424=ADVANCED_FACE('F1158',(#1423),#1412,.F.);
#1425=CARTESIAN_POINT('',(40.6196419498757,0.,-43.7337831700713));
#1426=DIRECTION('',(1.,0.,0.));
#1427=DIRECTION('',(0.,0.,-1.));
#1428=AXIS2_PLACEMENT_3D('',#1425,#1426,#1427);
#1429=PLANE('',#1428);
#1430=ORIENTED_EDGE('',*,*,#841,.T.);
#1431=ORIENTED_EDGE('',*,*,#710,.T.);
#1432=ORIENTED_EDGE('',*,*,#1417,.F.);
#1433=ORIENTED_EDGE('',*,*,#1161,.F.);
#1434=EDGE_LOOP('',(#1430,#1431,#1432,#1433));
#1435=FACE_BOUND('',#1434,.T.);
#1436=ADVANCED_FACE('F1153',(#1435),#1429,.F.);
#1437=CARTESIAN_POINT('',(37.3006394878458,6.00000000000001,11.7130463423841));
#1438=DIRECTION('',(0.,1.,0.));
#1439=DIRECTION('',(0.,0.,1.));
#1440=AXIS2_PLACEMENT_3D('',#1437,#1438,#1439);
#1441=PLANE('',#1440);
#1442=ORIENTED_EDGE('',*,*,#260,.T.);
#1443=DIRECTION('',(-1.,0.,0.));
#1444=VECTOR('',#1443,1.);
#1445=CARTESIAN_POINT('',(37.3006394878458,6.00000000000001,-18.7130463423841));
#1446=LINE('',#1445,#1444);
#1447=EDGE_CURVE('E753',#249,#448,#1446,.T.);
#1448=ORIENTED_EDGE('',*,*,#1447,.T.);
#1449=ORIENTED_EDGE('',*,*,#449,.F.);
#1450=DIRECTION('',(1.,0.,0.));
#1451=VECTOR('',#1450,1.);
#1452=CARTESIAN_POINT('',(37.3006394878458,6.00000000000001,18.7130463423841));
#1453=LINE('',#1452,#1451);
#1454=EDGE_CURVE('E456',#446,#259,#1453,.T.);
#1455=ORIENTED_EDGE('',*,*,#1454,.T.);
#1456=EDGE_LOOP('',(#1442,#1448,#1449,#1455));
#1457=FACE_BOUND('',#1456,.T.);
#1458=ADVANCED_FACE('F756',(#1457),#1441,.T.);
#1459=CARTESIAN_POINT('',(37.3006394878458,48.,-11.7130463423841));
#1460=DIRECTION('',(0.,-1.,0.));
#1461=DIRECTION('',(0.,0.,-1.));
#1462=AXIS2_PLACEMENT_3D('',#1459,#1460,#1461);
#1463=CYLINDRICAL_SURFACE('',#1462,7.);
#1464=DIRECTION('',(0.,-1.,0.));
#1465=VECTOR('',#1464,1.);
#1466=CARTESIAN_POINT('',(30.3006394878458,48.,-11.7130463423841));
#1467=LINE('',#1466,#1465);
#1468=EDGE_CURVE('E715',#318,#525,#1467,.T.);
#1469=ORIENTED_EDGE('',*,*,#1468,.T.);
#1470=ORIENTED_EDGE('',*,*,#526,.T.);
#1471=DIRECTION('',(0.,-1.,0.));
#1472=VECTOR('',#1471,1.);
#1473=CARTESIAN_POINT('',(37.3006394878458,48.,-18.7130463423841));
#1474=LINE('',#1473,#1472);
#1475=EDGE_CURVE('E713',#320,#514,#1474,.T.);
#1476=ORIENTED_EDGE('',*,*,#1475,.F.);
#1477=ORIENTED_EDGE('',*,*,#321,.F.);
#1478=EDGE_LOOP('',(#1469,#1470,#1476,#1477));
#1479=FACE_BOUND('',#1478,.T.);
#1480=ADVANCED_FACE('F712',(#1479),#1463,.F.);
#1481=CARTESIAN_POINT('',(30.3006394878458,48.,-11.7130463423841));
#1482=DIRECTION('',(1.,0.,0.));
#1483=DIRECTION('',(0.,0.,-1.));
#1484=AXIS2_PLACEMENT_3D('',#1481,#1482,#1483);
#1485=PLANE('',#1484);
#1486=DIRECTION('',(0.,-1.,0.));
#1487=VECTOR('',#1486,1.);
#1488=CARTESIAN_POINT('',(30.3006394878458,48.,11.7130463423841));
#1489=LINE('',#1488,#1487);
#1490=EDGE_CURVE('E447',#381,#533,#1489,.T.);
#1491=ORIENTED_EDGE('',*,*,#1490,.T.);
#1492=ORIENTED_EDGE('',*,*,#534,.T.);
#1493=ORIENTED_EDGE('',*,*,#1468,.F.);
#1494=ORIENTED_EDGE('',*,*,#388,.F.);
#1495=EDGE_LOOP('',(#1491,#1492,#1493,#1494));
#1496=FACE_BOUND('',#1495,.T.);
#1497=ADVANCED_FACE('F772',(#1496),#1485,.T.);
#1498=CARTESIAN_POINT('',(37.3006394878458,48.,11.7130463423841));
#1499=DIRECTION('',(0.,-1.,0.));
#1500=DIRECTION('',(0.,0.,-1.));
#1501=AXIS2_PLACEMENT_3D('',#1498,#1499,#1500);
#1502=CYLINDRICAL_SURFACE('',#1501,7.);
#1503=DIRECTION('',(0.,-1.,0.));
#1504=VECTOR('',#1503,1.);
#1505=CARTESIAN_POINT('',(37.3006394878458,48.,18.7130463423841));
#1506=LINE('',#1505,#1504);
#1507=EDGE_CURVE('E444',#372,#542,#1506,.T.);
#1508=ORIENTED_EDGE('',*,*,#1507,.T.);
#1509=ORIENTED_EDGE('',*,*,#543,.T.);
#1510=ORIENTED_EDGE('',*,*,#1490,.F.);
#1511=ORIENTED_EDGE('',*,*,#382,.F.);
#1512=EDGE_LOOP('',(#1508,#1509,#1510,#1511));
#1513=FACE_BOUND('',#1512,.T.);
#1514=ADVANCED_FACE('F443',(#1513),#1502,.F.);
#1515=CARTESIAN_POINT('',(37.3006394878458,48.,-18.7130463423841));
#1516=DIRECTION('',(0.,0.,1.));
#1517=DIRECTION('',(1.,0.,0.));
#1518=AXIS2_PLACEMENT_3D('',#1515,#1516,#1517);
#1519=PLANE('',#1518);
#1520=ORIENTED_EDGE('',*,*,#252,.T.);
#1521=ORIENTED_EDGE('',*,*,#404,.F.);
#1522=ORIENTED_EDGE('',*,*,#329,.F.);
#1523=ORIENTED_EDGE('',*,*,#1475,.T.);
#1524=ORIENTED_EDGE('',*,*,#517,.T.);
#1525=ORIENTED_EDGE('',*,*,#600,.T.);
#1526=ORIENTED_EDGE('',*,*,#457,.F.);
#1527=ORIENTED_EDGE('',*,*,#1447,.F.);
#1528=EDGE_LOOP('',(#1520,#1521,#1522,#1523,#1524,#1525,#1526,#1527));
#1529=FACE_BOUND('',#1528,.T.);
#1530=ADVANCED_FACE('F720',(#1529),#1519,.T.);
#1531=CARTESIAN_POINT('',(37.3006394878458,48.,18.7130463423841));
#1532=DIRECTION('',(0.,0.,-1.));
#1533=DIRECTION('',(-1.,0.,0.));
#1534=AXIS2_PLACEMENT_3D('',#1531,#1532,#1533);
#1535=PLANE('',#1534);
#1536=ORIENTED_EDGE('',*,*,#268,.T.);
#1537=ORIENTED_EDGE('',*,*,#1454,.F.);
#1538=ORIENTED_EDGE('',*,*,#499,.F.);
#1539=ORIENTED_EDGE('',*,*,#619,.T.);
#1540=ORIENTED_EDGE('',*,*,#551,.T.);
#1541=ORIENTED_EDGE('',*,*,#1507,.F.);
#1542=ORIENTED_EDGE('',*,*,#373,.F.);
#1543=ORIENTED_EDGE('',*,*,#423,.F.);
#1544=EDGE_LOOP('',(#1536,#1537,#1538,#1539,#1540,#1541,#1542,#1543));
#1545=FACE_BOUND('',#1544,.T.);
#1546=ADVANCED_FACE('F453',(#1545),#1535,.T.);
#1547=CLOSED_SHELL('',(#306,#392,#416,#435,#503,#589,#613,#632,#672,#740,#780,#898,#916,#940,
#958,#969,#986,#1004,#1022,#1040,#1057,#1074,#1086,#1117,#1171,#1202,#1220,#1244,#1262,#1273,
#1290,#1308,#1326,#1344,#1361,#1378,#1390,#1407,#1424,#1436,#1458,#1480,#1497,#1514,#1530,#1546));
#1548=MANIFOLD_SOLID_BREP('B6',#1547);
#1549=ADVANCED_BREP_SHAPE_REPRESENTATION('',(#18,#238,#1548),#14);
#1550=SHAPE_DEFINITION_REPRESENTATION(#9,#1549);
ENDSEC;
END-ISO-10303-21;
